VERSION 5.7 ;
BUSBITCHARS "[]" ;
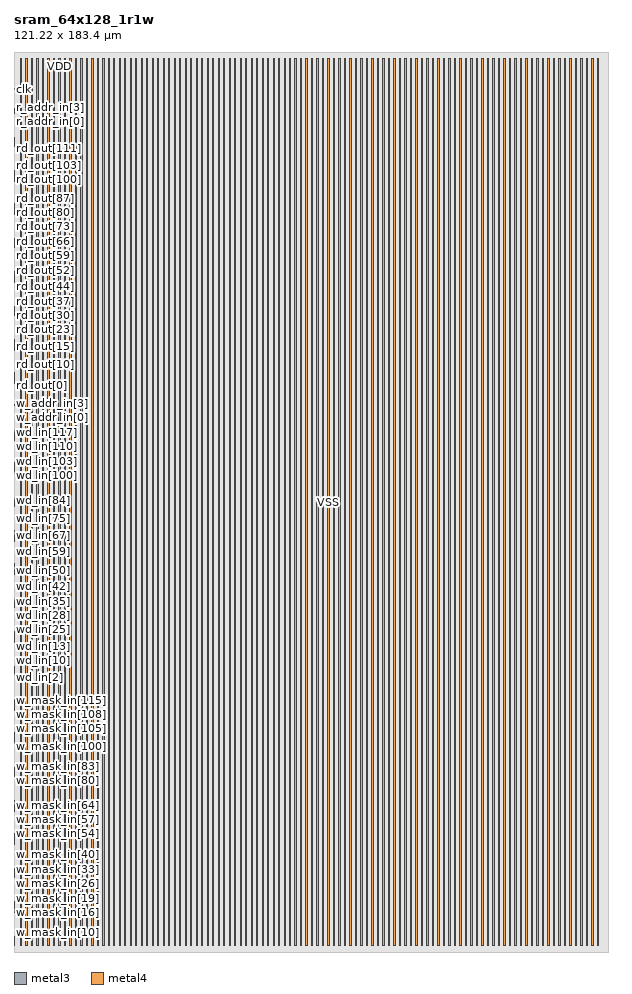
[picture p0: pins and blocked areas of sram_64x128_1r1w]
MACRO sram_64x128_1r1w
  FOREIGN sram_64x128_1r1w 0 0 ;
  SYMMETRY X Y R90 ;
  SIZE 121.220 BY 183.400 ;
  CLASS BLOCK ;
  PIN w_mask_in[0]
    DIRECTION INPUT ;
    USE SIGNAL ;
    SHAPE ABUTMENT ;
    PORT
      LAYER metal3 ;
      RECT 0.000 1.365 0.070 1.435 ;
    END
  END w_mask_in[0]
  PIN w_mask_in[1]
    DIRECTION INPUT ;
    USE SIGNAL ;
    SHAPE ABUTMENT ;
    PORT
      LAYER metal3 ;
      RECT 0.000 1.785 0.070 1.855 ;
    END
  END w_mask_in[1]
  PIN w_mask_in[2]
    DIRECTION INPUT ;
    USE SIGNAL ;
    SHAPE ABUTMENT ;
    PORT
      LAYER metal3 ;
      RECT 0.000 2.205 0.070 2.275 ;
    END
  END w_mask_in[2]
  PIN w_mask_in[3]
    DIRECTION INPUT ;
    USE SIGNAL ;
    SHAPE ABUTMENT ;
    PORT
      LAYER metal3 ;
      RECT 0.000 2.625 0.070 2.695 ;
    END
  END w_mask_in[3]
  PIN w_mask_in[4]
    DIRECTION INPUT ;
    USE SIGNAL ;
    SHAPE ABUTMENT ;
    PORT
      LAYER metal3 ;
      RECT 0.000 3.045 0.070 3.115 ;
    END
  END w_mask_in[4]
  PIN w_mask_in[5]
    DIRECTION INPUT ;
    USE SIGNAL ;
    SHAPE ABUTMENT ;
    PORT
      LAYER metal3 ;
      RECT 0.000 3.465 0.070 3.535 ;
    END
  END w_mask_in[5]
  PIN w_mask_in[6]
    DIRECTION INPUT ;
    USE SIGNAL ;
    SHAPE ABUTMENT ;
    PORT
      LAYER metal3 ;
      RECT 0.000 3.885 0.070 3.955 ;
    END
  END w_mask_in[6]
  PIN w_mask_in[7]
    DIRECTION INPUT ;
    USE SIGNAL ;
    SHAPE ABUTMENT ;
    PORT
      LAYER metal3 ;
      RECT 0.000 4.305 0.070 4.375 ;
    END
  END w_mask_in[7]
  PIN w_mask_in[8]
    DIRECTION INPUT ;
    USE SIGNAL ;
    SHAPE ABUTMENT ;
    PORT
      LAYER metal3 ;
      RECT 0.000 4.725 0.070 4.795 ;
    END
  END w_mask_in[8]
  PIN w_mask_in[9]
    DIRECTION INPUT ;
    USE SIGNAL ;
    SHAPE ABUTMENT ;
    PORT
      LAYER metal3 ;
      RECT 0.000 5.145 0.070 5.215 ;
    END
  END w_mask_in[9]
  PIN w_mask_in[10]
    DIRECTION INPUT ;
    USE SIGNAL ;
    SHAPE ABUTMENT ;
    PORT
      LAYER metal3 ;
      RECT 0.000 5.565 0.070 5.635 ;
    END
  END w_mask_in[10]
  PIN w_mask_in[11]
    DIRECTION INPUT ;
    USE SIGNAL ;
    SHAPE ABUTMENT ;
    PORT
      LAYER metal3 ;
      RECT 0.000 5.985 0.070 6.055 ;
    END
  END w_mask_in[11]
  PIN w_mask_in[12]
    DIRECTION INPUT ;
    USE SIGNAL ;
    SHAPE ABUTMENT ;
    PORT
      LAYER metal3 ;
      RECT 0.000 6.405 0.070 6.475 ;
    END
  END w_mask_in[12]
  PIN w_mask_in[13]
    DIRECTION INPUT ;
    USE SIGNAL ;
    SHAPE ABUTMENT ;
    PORT
      LAYER metal3 ;
      RECT 0.000 6.825 0.070 6.895 ;
    END
  END w_mask_in[13]
  PIN w_mask_in[14]
    DIRECTION INPUT ;
    USE SIGNAL ;
    SHAPE ABUTMENT ;
    PORT
      LAYER metal3 ;
      RECT 0.000 7.245 0.070 7.315 ;
    END
  END w_mask_in[14]
  PIN w_mask_in[15]
    DIRECTION INPUT ;
    USE SIGNAL ;
    SHAPE ABUTMENT ;
    PORT
      LAYER metal3 ;
      RECT 0.000 7.665 0.070 7.735 ;
    END
  END w_mask_in[15]
  PIN w_mask_in[16]
    DIRECTION INPUT ;
    USE SIGNAL ;
    SHAPE ABUTMENT ;
    PORT
      LAYER metal3 ;
      RECT 0.000 8.085 0.070 8.155 ;
    END
  END w_mask_in[16]
  PIN w_mask_in[17]
    DIRECTION INPUT ;
    USE SIGNAL ;
    SHAPE ABUTMENT ;
    PORT
      LAYER metal3 ;
      RECT 0.000 8.505 0.070 8.575 ;
    END
  END w_mask_in[17]
  PIN w_mask_in[18]
    DIRECTION INPUT ;
    USE SIGNAL ;
    SHAPE ABUTMENT ;
    PORT
      LAYER metal3 ;
      RECT 0.000 8.925 0.070 8.995 ;
    END
  END w_mask_in[18]
  PIN w_mask_in[19]
    DIRECTION INPUT ;
    USE SIGNAL ;
    SHAPE ABUTMENT ;
    PORT
      LAYER metal3 ;
      RECT 0.000 9.345 0.070 9.415 ;
    END
  END w_mask_in[19]
  PIN w_mask_in[20]
    DIRECTION INPUT ;
    USE SIGNAL ;
    SHAPE ABUTMENT ;
    PORT
      LAYER metal3 ;
      RECT 0.000 9.765 0.070 9.835 ;
    END
  END w_mask_in[20]
  PIN w_mask_in[21]
    DIRECTION INPUT ;
    USE SIGNAL ;
    SHAPE ABUTMENT ;
    PORT
      LAYER metal3 ;
      RECT 0.000 10.185 0.070 10.255 ;
    END
  END w_mask_in[21]
  PIN w_mask_in[22]
    DIRECTION INPUT ;
    USE SIGNAL ;
    SHAPE ABUTMENT ;
    PORT
      LAYER metal3 ;
      RECT 0.000 10.605 0.070 10.675 ;
    END
  END w_mask_in[22]
  PIN w_mask_in[23]
    DIRECTION INPUT ;
    USE SIGNAL ;
    SHAPE ABUTMENT ;
    PORT
      LAYER metal3 ;
      RECT 0.000 11.025 0.070 11.095 ;
    END
  END w_mask_in[23]
  PIN w_mask_in[24]
    DIRECTION INPUT ;
    USE SIGNAL ;
    SHAPE ABUTMENT ;
    PORT
      LAYER metal3 ;
      RECT 0.000 11.445 0.070 11.515 ;
    END
  END w_mask_in[24]
  PIN w_mask_in[25]
    DIRECTION INPUT ;
    USE SIGNAL ;
    SHAPE ABUTMENT ;
    PORT
      LAYER metal3 ;
      RECT 0.000 11.865 0.070 11.935 ;
    END
  END w_mask_in[25]
  PIN w_mask_in[26]
    DIRECTION INPUT ;
    USE SIGNAL ;
    SHAPE ABUTMENT ;
    PORT
      LAYER metal3 ;
      RECT 0.000 12.285 0.070 12.355 ;
    END
  END w_mask_in[26]
  PIN w_mask_in[27]
    DIRECTION INPUT ;
    USE SIGNAL ;
    SHAPE ABUTMENT ;
    PORT
      LAYER metal3 ;
      RECT 0.000 12.705 0.070 12.775 ;
    END
  END w_mask_in[27]
  PIN w_mask_in[28]
    DIRECTION INPUT ;
    USE SIGNAL ;
    SHAPE ABUTMENT ;
    PORT
      LAYER metal3 ;
      RECT 0.000 13.125 0.070 13.195 ;
    END
  END w_mask_in[28]
  PIN w_mask_in[29]
    DIRECTION INPUT ;
    USE SIGNAL ;
    SHAPE ABUTMENT ;
    PORT
      LAYER metal3 ;
      RECT 0.000 13.545 0.070 13.615 ;
    END
  END w_mask_in[29]
  PIN w_mask_in[30]
    DIRECTION INPUT ;
    USE SIGNAL ;
    SHAPE ABUTMENT ;
    PORT
      LAYER metal3 ;
      RECT 0.000 13.965 0.070 14.035 ;
    END
  END w_mask_in[30]
  PIN w_mask_in[31]
    DIRECTION INPUT ;
    USE SIGNAL ;
    SHAPE ABUTMENT ;
    PORT
      LAYER metal3 ;
      RECT 0.000 14.385 0.070 14.455 ;
    END
  END w_mask_in[31]
  PIN w_mask_in[32]
    DIRECTION INPUT ;
    USE SIGNAL ;
    SHAPE ABUTMENT ;
    PORT
      LAYER metal3 ;
      RECT 0.000 14.805 0.070 14.875 ;
    END
  END w_mask_in[32]
  PIN w_mask_in[33]
    DIRECTION INPUT ;
    USE SIGNAL ;
    SHAPE ABUTMENT ;
    PORT
      LAYER metal3 ;
      RECT 0.000 15.225 0.070 15.295 ;
    END
  END w_mask_in[33]
  PIN w_mask_in[34]
    DIRECTION INPUT ;
    USE SIGNAL ;
    SHAPE ABUTMENT ;
    PORT
      LAYER metal3 ;
      RECT 0.000 15.645 0.070 15.715 ;
    END
  END w_mask_in[34]
  PIN w_mask_in[35]
    DIRECTION INPUT ;
    USE SIGNAL ;
    SHAPE ABUTMENT ;
    PORT
      LAYER metal3 ;
      RECT 0.000 16.065 0.070 16.135 ;
    END
  END w_mask_in[35]
  PIN w_mask_in[36]
    DIRECTION INPUT ;
    USE SIGNAL ;
    SHAPE ABUTMENT ;
    PORT
      LAYER metal3 ;
      RECT 0.000 16.485 0.070 16.555 ;
    END
  END w_mask_in[36]
  PIN w_mask_in[37]
    DIRECTION INPUT ;
    USE SIGNAL ;
    SHAPE ABUTMENT ;
    PORT
      LAYER metal3 ;
      RECT 0.000 16.905 0.070 16.975 ;
    END
  END w_mask_in[37]
  PIN w_mask_in[38]
    DIRECTION INPUT ;
    USE SIGNAL ;
    SHAPE ABUTMENT ;
    PORT
      LAYER metal3 ;
      RECT 0.000 17.325 0.070 17.395 ;
    END
  END w_mask_in[38]
  PIN w_mask_in[39]
    DIRECTION INPUT ;
    USE SIGNAL ;
    SHAPE ABUTMENT ;
    PORT
      LAYER metal3 ;
      RECT 0.000 17.745 0.070 17.815 ;
    END
  END w_mask_in[39]
  PIN w_mask_in[40]
    DIRECTION INPUT ;
    USE SIGNAL ;
    SHAPE ABUTMENT ;
    PORT
      LAYER metal3 ;
      RECT 0.000 18.165 0.070 18.235 ;
    END
  END w_mask_in[40]
  PIN w_mask_in[41]
    DIRECTION INPUT ;
    USE SIGNAL ;
    SHAPE ABUTMENT ;
    PORT
      LAYER metal3 ;
      RECT 0.000 18.585 0.070 18.655 ;
    END
  END w_mask_in[41]
  PIN w_mask_in[42]
    DIRECTION INPUT ;
    USE SIGNAL ;
    SHAPE ABUTMENT ;
    PORT
      LAYER metal3 ;
      RECT 0.000 19.005 0.070 19.075 ;
    END
  END w_mask_in[42]
  PIN w_mask_in[43]
    DIRECTION INPUT ;
    USE SIGNAL ;
    SHAPE ABUTMENT ;
    PORT
      LAYER metal3 ;
      RECT 0.000 19.425 0.070 19.495 ;
    END
  END w_mask_in[43]
  PIN w_mask_in[44]
    DIRECTION INPUT ;
    USE SIGNAL ;
    SHAPE ABUTMENT ;
    PORT
      LAYER metal3 ;
      RECT 0.000 19.845 0.070 19.915 ;
    END
  END w_mask_in[44]
  PIN w_mask_in[45]
    DIRECTION INPUT ;
    USE SIGNAL ;
    SHAPE ABUTMENT ;
    PORT
      LAYER metal3 ;
      RECT 0.000 20.265 0.070 20.335 ;
    END
  END w_mask_in[45]
  PIN w_mask_in[46]
    DIRECTION INPUT ;
    USE SIGNAL ;
    SHAPE ABUTMENT ;
    PORT
      LAYER metal3 ;
      RECT 0.000 20.685 0.070 20.755 ;
    END
  END w_mask_in[46]
  PIN w_mask_in[47]
    DIRECTION INPUT ;
    USE SIGNAL ;
    SHAPE ABUTMENT ;
    PORT
      LAYER metal3 ;
      RECT 0.000 21.105 0.070 21.175 ;
    END
  END w_mask_in[47]
  PIN w_mask_in[48]
    DIRECTION INPUT ;
    USE SIGNAL ;
    SHAPE ABUTMENT ;
    PORT
      LAYER metal3 ;
      RECT 0.000 21.525 0.070 21.595 ;
    END
  END w_mask_in[48]
  PIN w_mask_in[49]
    DIRECTION INPUT ;
    USE SIGNAL ;
    SHAPE ABUTMENT ;
    PORT
      LAYER metal3 ;
      RECT 0.000 21.945 0.070 22.015 ;
    END
  END w_mask_in[49]
  PIN w_mask_in[50]
    DIRECTION INPUT ;
    USE SIGNAL ;
    SHAPE ABUTMENT ;
    PORT
      LAYER metal3 ;
      RECT 0.000 22.365 0.070 22.435 ;
    END
  END w_mask_in[50]
  PIN w_mask_in[51]
    DIRECTION INPUT ;
    USE SIGNAL ;
    SHAPE ABUTMENT ;
    PORT
      LAYER metal3 ;
      RECT 0.000 22.785 0.070 22.855 ;
    END
  END w_mask_in[51]
  PIN w_mask_in[52]
    DIRECTION INPUT ;
    USE SIGNAL ;
    SHAPE ABUTMENT ;
    PORT
      LAYER metal3 ;
      RECT 0.000 23.205 0.070 23.275 ;
    END
  END w_mask_in[52]
  PIN w_mask_in[53]
    DIRECTION INPUT ;
    USE SIGNAL ;
    SHAPE ABUTMENT ;
    PORT
      LAYER metal3 ;
      RECT 0.000 23.625 0.070 23.695 ;
    END
  END w_mask_in[53]
  PIN w_mask_in[54]
    DIRECTION INPUT ;
    USE SIGNAL ;
    SHAPE ABUTMENT ;
    PORT
      LAYER metal3 ;
      RECT 0.000 24.045 0.070 24.115 ;
    END
  END w_mask_in[54]
  PIN w_mask_in[55]
    DIRECTION INPUT ;
    USE SIGNAL ;
    SHAPE ABUTMENT ;
    PORT
      LAYER metal3 ;
      RECT 0.000 24.465 0.070 24.535 ;
    END
  END w_mask_in[55]
  PIN w_mask_in[56]
    DIRECTION INPUT ;
    USE SIGNAL ;
    SHAPE ABUTMENT ;
    PORT
      LAYER metal3 ;
      RECT 0.000 24.885 0.070 24.955 ;
    END
  END w_mask_in[56]
  PIN w_mask_in[57]
    DIRECTION INPUT ;
    USE SIGNAL ;
    SHAPE ABUTMENT ;
    PORT
      LAYER metal3 ;
      RECT 0.000 25.305 0.070 25.375 ;
    END
  END w_mask_in[57]
  PIN w_mask_in[58]
    DIRECTION INPUT ;
    USE SIGNAL ;
    SHAPE ABUTMENT ;
    PORT
      LAYER metal3 ;
      RECT 0.000 25.725 0.070 25.795 ;
    END
  END w_mask_in[58]
  PIN w_mask_in[59]
    DIRECTION INPUT ;
    USE SIGNAL ;
    SHAPE ABUTMENT ;
    PORT
      LAYER metal3 ;
      RECT 0.000 26.145 0.070 26.215 ;
    END
  END w_mask_in[59]
  PIN w_mask_in[60]
    DIRECTION INPUT ;
    USE SIGNAL ;
    SHAPE ABUTMENT ;
    PORT
      LAYER metal3 ;
      RECT 0.000 26.565 0.070 26.635 ;
    END
  END w_mask_in[60]
  PIN w_mask_in[61]
    DIRECTION INPUT ;
    USE SIGNAL ;
    SHAPE ABUTMENT ;
    PORT
      LAYER metal3 ;
      RECT 0.000 26.985 0.070 27.055 ;
    END
  END w_mask_in[61]
  PIN w_mask_in[62]
    DIRECTION INPUT ;
    USE SIGNAL ;
    SHAPE ABUTMENT ;
    PORT
      LAYER metal3 ;
      RECT 0.000 27.405 0.070 27.475 ;
    END
  END w_mask_in[62]
  PIN w_mask_in[63]
    DIRECTION INPUT ;
    USE SIGNAL ;
    SHAPE ABUTMENT ;
    PORT
      LAYER metal3 ;
      RECT 0.000 27.825 0.070 27.895 ;
    END
  END w_mask_in[63]
  PIN w_mask_in[64]
    DIRECTION INPUT ;
    USE SIGNAL ;
    SHAPE ABUTMENT ;
    PORT
      LAYER metal3 ;
      RECT 0.000 28.245 0.070 28.315 ;
    END
  END w_mask_in[64]
  PIN w_mask_in[65]
    DIRECTION INPUT ;
    USE SIGNAL ;
    SHAPE ABUTMENT ;
    PORT
      LAYER metal3 ;
      RECT 0.000 28.665 0.070 28.735 ;
    END
  END w_mask_in[65]
  PIN w_mask_in[66]
    DIRECTION INPUT ;
    USE SIGNAL ;
    SHAPE ABUTMENT ;
    PORT
      LAYER metal3 ;
      RECT 0.000 29.085 0.070 29.155 ;
    END
  END w_mask_in[66]
  PIN w_mask_in[67]
    DIRECTION INPUT ;
    USE SIGNAL ;
    SHAPE ABUTMENT ;
    PORT
      LAYER metal3 ;
      RECT 0.000 29.505 0.070 29.575 ;
    END
  END w_mask_in[67]
  PIN w_mask_in[68]
    DIRECTION INPUT ;
    USE SIGNAL ;
    SHAPE ABUTMENT ;
    PORT
      LAYER metal3 ;
      RECT 0.000 29.925 0.070 29.995 ;
    END
  END w_mask_in[68]
  PIN w_mask_in[69]
    DIRECTION INPUT ;
    USE SIGNAL ;
    SHAPE ABUTMENT ;
    PORT
      LAYER metal3 ;
      RECT 0.000 30.345 0.070 30.415 ;
    END
  END w_mask_in[69]
  PIN w_mask_in[70]
    DIRECTION INPUT ;
    USE SIGNAL ;
    SHAPE ABUTMENT ;
    PORT
      LAYER metal3 ;
      RECT 0.000 30.765 0.070 30.835 ;
    END
  END w_mask_in[70]
  PIN w_mask_in[71]
    DIRECTION INPUT ;
    USE SIGNAL ;
    SHAPE ABUTMENT ;
    PORT
      LAYER metal3 ;
      RECT 0.000 31.185 0.070 31.255 ;
    END
  END w_mask_in[71]
  PIN w_mask_in[72]
    DIRECTION INPUT ;
    USE SIGNAL ;
    SHAPE ABUTMENT ;
    PORT
      LAYER metal3 ;
      RECT 0.000 31.605 0.070 31.675 ;
    END
  END w_mask_in[72]
  PIN w_mask_in[73]
    DIRECTION INPUT ;
    USE SIGNAL ;
    SHAPE ABUTMENT ;
    PORT
      LAYER metal3 ;
      RECT 0.000 32.025 0.070 32.095 ;
    END
  END w_mask_in[73]
  PIN w_mask_in[74]
    DIRECTION INPUT ;
    USE SIGNAL ;
    SHAPE ABUTMENT ;
    PORT
      LAYER metal3 ;
      RECT 0.000 32.445 0.070 32.515 ;
    END
  END w_mask_in[74]
  PIN w_mask_in[75]
    DIRECTION INPUT ;
    USE SIGNAL ;
    SHAPE ABUTMENT ;
    PORT
      LAYER metal3 ;
      RECT 0.000 32.865 0.070 32.935 ;
    END
  END w_mask_in[75]
  PIN w_mask_in[76]
    DIRECTION INPUT ;
    USE SIGNAL ;
    SHAPE ABUTMENT ;
    PORT
      LAYER metal3 ;
      RECT 0.000 33.285 0.070 33.355 ;
    END
  END w_mask_in[76]
  PIN w_mask_in[77]
    DIRECTION INPUT ;
    USE SIGNAL ;
    SHAPE ABUTMENT ;
    PORT
      LAYER metal3 ;
      RECT 0.000 33.705 0.070 33.775 ;
    END
  END w_mask_in[77]
  PIN w_mask_in[78]
    DIRECTION INPUT ;
    USE SIGNAL ;
    SHAPE ABUTMENT ;
    PORT
      LAYER metal3 ;
      RECT 0.000 34.125 0.070 34.195 ;
    END
  END w_mask_in[78]
  PIN w_mask_in[79]
    DIRECTION INPUT ;
    USE SIGNAL ;
    SHAPE ABUTMENT ;
    PORT
      LAYER metal3 ;
      RECT 0.000 34.545 0.070 34.615 ;
    END
  END w_mask_in[79]
  PIN w_mask_in[80]
    DIRECTION INPUT ;
    USE SIGNAL ;
    SHAPE ABUTMENT ;
    PORT
      LAYER metal3 ;
      RECT 0.000 34.965 0.070 35.035 ;
    END
  END w_mask_in[80]
  PIN w_mask_in[81]
    DIRECTION INPUT ;
    USE SIGNAL ;
    SHAPE ABUTMENT ;
    PORT
      LAYER metal3 ;
      RECT 0.000 35.385 0.070 35.455 ;
    END
  END w_mask_in[81]
  PIN w_mask_in[82]
    DIRECTION INPUT ;
    USE SIGNAL ;
    SHAPE ABUTMENT ;
    PORT
      LAYER metal3 ;
      RECT 0.000 35.805 0.070 35.875 ;
    END
  END w_mask_in[82]
  PIN w_mask_in[83]
    DIRECTION INPUT ;
    USE SIGNAL ;
    SHAPE ABUTMENT ;
    PORT
      LAYER metal3 ;
      RECT 0.000 36.225 0.070 36.295 ;
    END
  END w_mask_in[83]
  PIN w_mask_in[84]
    DIRECTION INPUT ;
    USE SIGNAL ;
    SHAPE ABUTMENT ;
    PORT
      LAYER metal3 ;
      RECT 0.000 36.645 0.070 36.715 ;
    END
  END w_mask_in[84]
  PIN w_mask_in[85]
    DIRECTION INPUT ;
    USE SIGNAL ;
    SHAPE ABUTMENT ;
    PORT
      LAYER metal3 ;
      RECT 0.000 37.065 0.070 37.135 ;
    END
  END w_mask_in[85]
  PIN w_mask_in[86]
    DIRECTION INPUT ;
    USE SIGNAL ;
    SHAPE ABUTMENT ;
    PORT
      LAYER metal3 ;
      RECT 0.000 37.485 0.070 37.555 ;
    END
  END w_mask_in[86]
  PIN w_mask_in[87]
    DIRECTION INPUT ;
    USE SIGNAL ;
    SHAPE ABUTMENT ;
    PORT
      LAYER metal3 ;
      RECT 0.000 37.905 0.070 37.975 ;
    END
  END w_mask_in[87]
  PIN w_mask_in[88]
    DIRECTION INPUT ;
    USE SIGNAL ;
    SHAPE ABUTMENT ;
    PORT
      LAYER metal3 ;
      RECT 0.000 38.325 0.070 38.395 ;
    END
  END w_mask_in[88]
  PIN w_mask_in[89]
    DIRECTION INPUT ;
    USE SIGNAL ;
    SHAPE ABUTMENT ;
    PORT
      LAYER metal3 ;
      RECT 0.000 38.745 0.070 38.815 ;
    END
  END w_mask_in[89]
  PIN w_mask_in[90]
    DIRECTION INPUT ;
    USE SIGNAL ;
    SHAPE ABUTMENT ;
    PORT
      LAYER metal3 ;
      RECT 0.000 39.165 0.070 39.235 ;
    END
  END w_mask_in[90]
  PIN w_mask_in[91]
    DIRECTION INPUT ;
    USE SIGNAL ;
    SHAPE ABUTMENT ;
    PORT
      LAYER metal3 ;
      RECT 0.000 39.585 0.070 39.655 ;
    END
  END w_mask_in[91]
  PIN w_mask_in[92]
    DIRECTION INPUT ;
    USE SIGNAL ;
    SHAPE ABUTMENT ;
    PORT
      LAYER metal3 ;
      RECT 0.000 40.005 0.070 40.075 ;
    END
  END w_mask_in[92]
  PIN w_mask_in[93]
    DIRECTION INPUT ;
    USE SIGNAL ;
    SHAPE ABUTMENT ;
    PORT
      LAYER metal3 ;
      RECT 0.000 40.425 0.070 40.495 ;
    END
  END w_mask_in[93]
  PIN w_mask_in[94]
    DIRECTION INPUT ;
    USE SIGNAL ;
    SHAPE ABUTMENT ;
    PORT
      LAYER metal3 ;
      RECT 0.000 40.845 0.070 40.915 ;
    END
  END w_mask_in[94]
  PIN w_mask_in[95]
    DIRECTION INPUT ;
    USE SIGNAL ;
    SHAPE ABUTMENT ;
    PORT
      LAYER metal3 ;
      RECT 0.000 41.265 0.070 41.335 ;
    END
  END w_mask_in[95]
  PIN w_mask_in[96]
    DIRECTION INPUT ;
    USE SIGNAL ;
    SHAPE ABUTMENT ;
    PORT
      LAYER metal3 ;
      RECT 0.000 41.685 0.070 41.755 ;
    END
  END w_mask_in[96]
  PIN w_mask_in[97]
    DIRECTION INPUT ;
    USE SIGNAL ;
    SHAPE ABUTMENT ;
    PORT
      LAYER metal3 ;
      RECT 0.000 42.105 0.070 42.175 ;
    END
  END w_mask_in[97]
  PIN w_mask_in[98]
    DIRECTION INPUT ;
    USE SIGNAL ;
    SHAPE ABUTMENT ;
    PORT
      LAYER metal3 ;
      RECT 0.000 42.525 0.070 42.595 ;
    END
  END w_mask_in[98]
  PIN w_mask_in[99]
    DIRECTION INPUT ;
    USE SIGNAL ;
    SHAPE ABUTMENT ;
    PORT
      LAYER metal3 ;
      RECT 0.000 42.945 0.070 43.015 ;
    END
  END w_mask_in[99]
  PIN w_mask_in[100]
    DIRECTION INPUT ;
    USE SIGNAL ;
    SHAPE ABUTMENT ;
    PORT
      LAYER metal3 ;
      RECT 0.000 43.365 0.070 43.435 ;
    END
  END w_mask_in[100]
  PIN w_mask_in[101]
    DIRECTION INPUT ;
    USE SIGNAL ;
    SHAPE ABUTMENT ;
    PORT
      LAYER metal3 ;
      RECT 0.000 43.785 0.070 43.855 ;
    END
  END w_mask_in[101]
  PIN w_mask_in[102]
    DIRECTION INPUT ;
    USE SIGNAL ;
    SHAPE ABUTMENT ;
    PORT
      LAYER metal3 ;
      RECT 0.000 44.205 0.070 44.275 ;
    END
  END w_mask_in[102]
  PIN w_mask_in[103]
    DIRECTION INPUT ;
    USE SIGNAL ;
    SHAPE ABUTMENT ;
    PORT
      LAYER metal3 ;
      RECT 0.000 44.625 0.070 44.695 ;
    END
  END w_mask_in[103]
  PIN w_mask_in[104]
    DIRECTION INPUT ;
    USE SIGNAL ;
    SHAPE ABUTMENT ;
    PORT
      LAYER metal3 ;
      RECT 0.000 45.045 0.070 45.115 ;
    END
  END w_mask_in[104]
  PIN w_mask_in[105]
    DIRECTION INPUT ;
    USE SIGNAL ;
    SHAPE ABUTMENT ;
    PORT
      LAYER metal3 ;
      RECT 0.000 45.465 0.070 45.535 ;
    END
  END w_mask_in[105]
  PIN w_mask_in[106]
    DIRECTION INPUT ;
    USE SIGNAL ;
    SHAPE ABUTMENT ;
    PORT
      LAYER metal3 ;
      RECT 0.000 45.885 0.070 45.955 ;
    END
  END w_mask_in[106]
  PIN w_mask_in[107]
    DIRECTION INPUT ;
    USE SIGNAL ;
    SHAPE ABUTMENT ;
    PORT
      LAYER metal3 ;
      RECT 0.000 46.305 0.070 46.375 ;
    END
  END w_mask_in[107]
  PIN w_mask_in[108]
    DIRECTION INPUT ;
    USE SIGNAL ;
    SHAPE ABUTMENT ;
    PORT
      LAYER metal3 ;
      RECT 0.000 46.725 0.070 46.795 ;
    END
  END w_mask_in[108]
  PIN w_mask_in[109]
    DIRECTION INPUT ;
    USE SIGNAL ;
    SHAPE ABUTMENT ;
    PORT
      LAYER metal3 ;
      RECT 0.000 47.145 0.070 47.215 ;
    END
  END w_mask_in[109]
  PIN w_mask_in[110]
    DIRECTION INPUT ;
    USE SIGNAL ;
    SHAPE ABUTMENT ;
    PORT
      LAYER metal3 ;
      RECT 0.000 47.565 0.070 47.635 ;
    END
  END w_mask_in[110]
  PIN w_mask_in[111]
    DIRECTION INPUT ;
    USE SIGNAL ;
    SHAPE ABUTMENT ;
    PORT
      LAYER metal3 ;
      RECT 0.000 47.985 0.070 48.055 ;
    END
  END w_mask_in[111]
  PIN w_mask_in[112]
    DIRECTION INPUT ;
    USE SIGNAL ;
    SHAPE ABUTMENT ;
    PORT
      LAYER metal3 ;
      RECT 0.000 48.405 0.070 48.475 ;
    END
  END w_mask_in[112]
  PIN w_mask_in[113]
    DIRECTION INPUT ;
    USE SIGNAL ;
    SHAPE ABUTMENT ;
    PORT
      LAYER metal3 ;
      RECT 0.000 48.825 0.070 48.895 ;
    END
  END w_mask_in[113]
  PIN w_mask_in[114]
    DIRECTION INPUT ;
    USE SIGNAL ;
    SHAPE ABUTMENT ;
    PORT
      LAYER metal3 ;
      RECT 0.000 49.245 0.070 49.315 ;
    END
  END w_mask_in[114]
  PIN w_mask_in[115]
    DIRECTION INPUT ;
    USE SIGNAL ;
    SHAPE ABUTMENT ;
    PORT
      LAYER metal3 ;
      RECT 0.000 49.665 0.070 49.735 ;
    END
  END w_mask_in[115]
  PIN w_mask_in[116]
    DIRECTION INPUT ;
    USE SIGNAL ;
    SHAPE ABUTMENT ;
    PORT
      LAYER metal3 ;
      RECT 0.000 50.085 0.070 50.155 ;
    END
  END w_mask_in[116]
  PIN w_mask_in[117]
    DIRECTION INPUT ;
    USE SIGNAL ;
    SHAPE ABUTMENT ;
    PORT
      LAYER metal3 ;
      RECT 0.000 50.505 0.070 50.575 ;
    END
  END w_mask_in[117]
  PIN w_mask_in[118]
    DIRECTION INPUT ;
    USE SIGNAL ;
    SHAPE ABUTMENT ;
    PORT
      LAYER metal3 ;
      RECT 0.000 50.925 0.070 50.995 ;
    END
  END w_mask_in[118]
  PIN w_mask_in[119]
    DIRECTION INPUT ;
    USE SIGNAL ;
    SHAPE ABUTMENT ;
    PORT
      LAYER metal3 ;
      RECT 0.000 51.345 0.070 51.415 ;
    END
  END w_mask_in[119]
  PIN w_mask_in[120]
    DIRECTION INPUT ;
    USE SIGNAL ;
    SHAPE ABUTMENT ;
    PORT
      LAYER metal3 ;
      RECT 0.000 51.765 0.070 51.835 ;
    END
  END w_mask_in[120]
  PIN w_mask_in[121]
    DIRECTION INPUT ;
    USE SIGNAL ;
    SHAPE ABUTMENT ;
    PORT
      LAYER metal3 ;
      RECT 0.000 52.185 0.070 52.255 ;
    END
  END w_mask_in[121]
  PIN w_mask_in[122]
    DIRECTION INPUT ;
    USE SIGNAL ;
    SHAPE ABUTMENT ;
    PORT
      LAYER metal3 ;
      RECT 0.000 52.605 0.070 52.675 ;
    END
  END w_mask_in[122]
  PIN w_mask_in[123]
    DIRECTION INPUT ;
    USE SIGNAL ;
    SHAPE ABUTMENT ;
    PORT
      LAYER metal3 ;
      RECT 0.000 53.025 0.070 53.095 ;
    END
  END w_mask_in[123]
  PIN w_mask_in[124]
    DIRECTION INPUT ;
    USE SIGNAL ;
    SHAPE ABUTMENT ;
    PORT
      LAYER metal3 ;
      RECT 0.000 53.445 0.070 53.515 ;
    END
  END w_mask_in[124]
  PIN w_mask_in[125]
    DIRECTION INPUT ;
    USE SIGNAL ;
    SHAPE ABUTMENT ;
    PORT
      LAYER metal3 ;
      RECT 0.000 53.865 0.070 53.935 ;
    END
  END w_mask_in[125]
  PIN w_mask_in[126]
    DIRECTION INPUT ;
    USE SIGNAL ;
    SHAPE ABUTMENT ;
    PORT
      LAYER metal3 ;
      RECT 0.000 54.285 0.070 54.355 ;
    END
  END w_mask_in[126]
  PIN w_mask_in[127]
    DIRECTION INPUT ;
    USE SIGNAL ;
    SHAPE ABUTMENT ;
    PORT
      LAYER metal3 ;
      RECT 0.000 54.705 0.070 54.775 ;
    END
  END w_mask_in[127]
  PIN wd_in[0]
    DIRECTION INPUT ;
    USE SIGNAL ;
    SHAPE ABUTMENT ;
    PORT
      LAYER metal3 ;
      RECT 0.000 55.125 0.070 55.195 ;
    END
  END wd_in[0]
  PIN wd_in[1]
    DIRECTION INPUT ;
    USE SIGNAL ;
    SHAPE ABUTMENT ;
    PORT
      LAYER metal3 ;
      RECT 0.000 55.545 0.070 55.615 ;
    END
  END wd_in[1]
  PIN wd_in[2]
    DIRECTION INPUT ;
    USE SIGNAL ;
    SHAPE ABUTMENT ;
    PORT
      LAYER metal3 ;
      RECT 0.000 55.965 0.070 56.035 ;
    END
  END wd_in[2]
  PIN wd_in[3]
    DIRECTION INPUT ;
    USE SIGNAL ;
    SHAPE ABUTMENT ;
    PORT
      LAYER metal3 ;
      RECT 0.000 56.385 0.070 56.455 ;
    END
  END wd_in[3]
  PIN wd_in[4]
    DIRECTION INPUT ;
    USE SIGNAL ;
    SHAPE ABUTMENT ;
    PORT
      LAYER metal3 ;
      RECT 0.000 56.805 0.070 56.875 ;
    END
  END wd_in[4]
  PIN wd_in[5]
    DIRECTION INPUT ;
    USE SIGNAL ;
    SHAPE ABUTMENT ;
    PORT
      LAYER metal3 ;
      RECT 0.000 57.225 0.070 57.295 ;
    END
  END wd_in[5]
  PIN wd_in[6]
    DIRECTION INPUT ;
    USE SIGNAL ;
    SHAPE ABUTMENT ;
    PORT
      LAYER metal3 ;
      RECT 0.000 57.645 0.070 57.715 ;
    END
  END wd_in[6]
  PIN wd_in[7]
    DIRECTION INPUT ;
    USE SIGNAL ;
    SHAPE ABUTMENT ;
    PORT
      LAYER metal3 ;
      RECT 0.000 58.065 0.070 58.135 ;
    END
  END wd_in[7]
  PIN wd_in[8]
    DIRECTION INPUT ;
    USE SIGNAL ;
    SHAPE ABUTMENT ;
    PORT
      LAYER metal3 ;
      RECT 0.000 58.485 0.070 58.555 ;
    END
  END wd_in[8]
  PIN wd_in[9]
    DIRECTION INPUT ;
    USE SIGNAL ;
    SHAPE ABUTMENT ;
    PORT
      LAYER metal3 ;
      RECT 0.000 58.905 0.070 58.975 ;
    END
  END wd_in[9]
  PIN wd_in[10]
    DIRECTION INPUT ;
    USE SIGNAL ;
    SHAPE ABUTMENT ;
    PORT
      LAYER metal3 ;
      RECT 0.000 59.325 0.070 59.395 ;
    END
  END wd_in[10]
  PIN wd_in[11]
    DIRECTION INPUT ;
    USE SIGNAL ;
    SHAPE ABUTMENT ;
    PORT
      LAYER metal3 ;
      RECT 0.000 59.745 0.070 59.815 ;
    END
  END wd_in[11]
  PIN wd_in[12]
    DIRECTION INPUT ;
    USE SIGNAL ;
    SHAPE ABUTMENT ;
    PORT
      LAYER metal3 ;
      RECT 0.000 60.165 0.070 60.235 ;
    END
  END wd_in[12]
  PIN wd_in[13]
    DIRECTION INPUT ;
    USE SIGNAL ;
    SHAPE ABUTMENT ;
    PORT
      LAYER metal3 ;
      RECT 0.000 60.585 0.070 60.655 ;
    END
  END wd_in[13]
  PIN wd_in[14]
    DIRECTION INPUT ;
    USE SIGNAL ;
    SHAPE ABUTMENT ;
    PORT
      LAYER metal3 ;
      RECT 0.000 61.005 0.070 61.075 ;
    END
  END wd_in[14]
  PIN wd_in[15]
    DIRECTION INPUT ;
    USE SIGNAL ;
    SHAPE ABUTMENT ;
    PORT
      LAYER metal3 ;
      RECT 0.000 61.425 0.070 61.495 ;
    END
  END wd_in[15]
  PIN wd_in[16]
    DIRECTION INPUT ;
    USE SIGNAL ;
    SHAPE ABUTMENT ;
    PORT
      LAYER metal3 ;
      RECT 0.000 61.845 0.070 61.915 ;
    END
  END wd_in[16]
  PIN wd_in[17]
    DIRECTION INPUT ;
    USE SIGNAL ;
    SHAPE ABUTMENT ;
    PORT
      LAYER metal3 ;
      RECT 0.000 62.265 0.070 62.335 ;
    END
  END wd_in[17]
  PIN wd_in[18]
    DIRECTION INPUT ;
    USE SIGNAL ;
    SHAPE ABUTMENT ;
    PORT
      LAYER metal3 ;
      RECT 0.000 62.685 0.070 62.755 ;
    END
  END wd_in[18]
  PIN wd_in[19]
    DIRECTION INPUT ;
    USE SIGNAL ;
    SHAPE ABUTMENT ;
    PORT
      LAYER metal3 ;
      RECT 0.000 63.105 0.070 63.175 ;
    END
  END wd_in[19]
  PIN wd_in[20]
    DIRECTION INPUT ;
    USE SIGNAL ;
    SHAPE ABUTMENT ;
    PORT
      LAYER metal3 ;
      RECT 0.000 63.525 0.070 63.595 ;
    END
  END wd_in[20]
  PIN wd_in[21]
    DIRECTION INPUT ;
    USE SIGNAL ;
    SHAPE ABUTMENT ;
    PORT
      LAYER metal3 ;
      RECT 0.000 63.945 0.070 64.015 ;
    END
  END wd_in[21]
  PIN wd_in[22]
    DIRECTION INPUT ;
    USE SIGNAL ;
    SHAPE ABUTMENT ;
    PORT
      LAYER metal3 ;
      RECT 0.000 64.365 0.070 64.435 ;
    END
  END wd_in[22]
  PIN wd_in[23]
    DIRECTION INPUT ;
    USE SIGNAL ;
    SHAPE ABUTMENT ;
    PORT
      LAYER metal3 ;
      RECT 0.000 64.785 0.070 64.855 ;
    END
  END wd_in[23]
  PIN wd_in[24]
    DIRECTION INPUT ;
    USE SIGNAL ;
    SHAPE ABUTMENT ;
    PORT
      LAYER metal3 ;
      RECT 0.000 65.205 0.070 65.275 ;
    END
  END wd_in[24]
  PIN wd_in[25]
    DIRECTION INPUT ;
    USE SIGNAL ;
    SHAPE ABUTMENT ;
    PORT
      LAYER metal3 ;
      RECT 0.000 65.625 0.070 65.695 ;
    END
  END wd_in[25]
  PIN wd_in[26]
    DIRECTION INPUT ;
    USE SIGNAL ;
    SHAPE ABUTMENT ;
    PORT
      LAYER metal3 ;
      RECT 0.000 66.045 0.070 66.115 ;
    END
  END wd_in[26]
  PIN wd_in[27]
    DIRECTION INPUT ;
    USE SIGNAL ;
    SHAPE ABUTMENT ;
    PORT
      LAYER metal3 ;
      RECT 0.000 66.465 0.070 66.535 ;
    END
  END wd_in[27]
  PIN wd_in[28]
    DIRECTION INPUT ;
    USE SIGNAL ;
    SHAPE ABUTMENT ;
    PORT
      LAYER metal3 ;
      RECT 0.000 66.885 0.070 66.955 ;
    END
  END wd_in[28]
  PIN wd_in[29]
    DIRECTION INPUT ;
    USE SIGNAL ;
    SHAPE ABUTMENT ;
    PORT
      LAYER metal3 ;
      RECT 0.000 67.305 0.070 67.375 ;
    END
  END wd_in[29]
  PIN wd_in[30]
    DIRECTION INPUT ;
    USE SIGNAL ;
    SHAPE ABUTMENT ;
    PORT
      LAYER metal3 ;
      RECT 0.000 67.725 0.070 67.795 ;
    END
  END wd_in[30]
  PIN wd_in[31]
    DIRECTION INPUT ;
    USE SIGNAL ;
    SHAPE ABUTMENT ;
    PORT
      LAYER metal3 ;
      RECT 0.000 68.145 0.070 68.215 ;
    END
  END wd_in[31]
  PIN wd_in[32]
    DIRECTION INPUT ;
    USE SIGNAL ;
    SHAPE ABUTMENT ;
    PORT
      LAYER metal3 ;
      RECT 0.000 68.565 0.070 68.635 ;
    END
  END wd_in[32]
  PIN wd_in[33]
    DIRECTION INPUT ;
    USE SIGNAL ;
    SHAPE ABUTMENT ;
    PORT
      LAYER metal3 ;
      RECT 0.000 68.985 0.070 69.055 ;
    END
  END wd_in[33]
  PIN wd_in[34]
    DIRECTION INPUT ;
    USE SIGNAL ;
    SHAPE ABUTMENT ;
    PORT
      LAYER metal3 ;
      RECT 0.000 69.405 0.070 69.475 ;
    END
  END wd_in[34]
  PIN wd_in[35]
    DIRECTION INPUT ;
    USE SIGNAL ;
    SHAPE ABUTMENT ;
    PORT
      LAYER metal3 ;
      RECT 0.000 69.825 0.070 69.895 ;
    END
  END wd_in[35]
  PIN wd_in[36]
    DIRECTION INPUT ;
    USE SIGNAL ;
    SHAPE ABUTMENT ;
    PORT
      LAYER metal3 ;
      RECT 0.000 70.245 0.070 70.315 ;
    END
  END wd_in[36]
  PIN wd_in[37]
    DIRECTION INPUT ;
    USE SIGNAL ;
    SHAPE ABUTMENT ;
    PORT
      LAYER metal3 ;
      RECT 0.000 70.665 0.070 70.735 ;
    END
  END wd_in[37]
  PIN wd_in[38]
    DIRECTION INPUT ;
    USE SIGNAL ;
    SHAPE ABUTMENT ;
    PORT
      LAYER metal3 ;
      RECT 0.000 71.085 0.070 71.155 ;
    END
  END wd_in[38]
  PIN wd_in[39]
    DIRECTION INPUT ;
    USE SIGNAL ;
    SHAPE ABUTMENT ;
    PORT
      LAYER metal3 ;
      RECT 0.000 71.505 0.070 71.575 ;
    END
  END wd_in[39]
  PIN wd_in[40]
    DIRECTION INPUT ;
    USE SIGNAL ;
    SHAPE ABUTMENT ;
    PORT
      LAYER metal3 ;
      RECT 0.000 71.925 0.070 71.995 ;
    END
  END wd_in[40]
  PIN wd_in[41]
    DIRECTION INPUT ;
    USE SIGNAL ;
    SHAPE ABUTMENT ;
    PORT
      LAYER metal3 ;
      RECT 0.000 72.345 0.070 72.415 ;
    END
  END wd_in[41]
  PIN wd_in[42]
    DIRECTION INPUT ;
    USE SIGNAL ;
    SHAPE ABUTMENT ;
    PORT
      LAYER metal3 ;
      RECT 0.000 72.765 0.070 72.835 ;
    END
  END wd_in[42]
  PIN wd_in[43]
    DIRECTION INPUT ;
    USE SIGNAL ;
    SHAPE ABUTMENT ;
    PORT
      LAYER metal3 ;
      RECT 0.000 73.185 0.070 73.255 ;
    END
  END wd_in[43]
  PIN wd_in[44]
    DIRECTION INPUT ;
    USE SIGNAL ;
    SHAPE ABUTMENT ;
    PORT
      LAYER metal3 ;
      RECT 0.000 73.605 0.070 73.675 ;
    END
  END wd_in[44]
  PIN wd_in[45]
    DIRECTION INPUT ;
    USE SIGNAL ;
    SHAPE ABUTMENT ;
    PORT
      LAYER metal3 ;
      RECT 0.000 74.025 0.070 74.095 ;
    END
  END wd_in[45]
  PIN wd_in[46]
    DIRECTION INPUT ;
    USE SIGNAL ;
    SHAPE ABUTMENT ;
    PORT
      LAYER metal3 ;
      RECT 0.000 74.445 0.070 74.515 ;
    END
  END wd_in[46]
  PIN wd_in[47]
    DIRECTION INPUT ;
    USE SIGNAL ;
    SHAPE ABUTMENT ;
    PORT
      LAYER metal3 ;
      RECT 0.000 74.865 0.070 74.935 ;
    END
  END wd_in[47]
  PIN wd_in[48]
    DIRECTION INPUT ;
    USE SIGNAL ;
    SHAPE ABUTMENT ;
    PORT
      LAYER metal3 ;
      RECT 0.000 75.285 0.070 75.355 ;
    END
  END wd_in[48]
  PIN wd_in[49]
    DIRECTION INPUT ;
    USE SIGNAL ;
    SHAPE ABUTMENT ;
    PORT
      LAYER metal3 ;
      RECT 0.000 75.705 0.070 75.775 ;
    END
  END wd_in[49]
  PIN wd_in[50]
    DIRECTION INPUT ;
    USE SIGNAL ;
    SHAPE ABUTMENT ;
    PORT
      LAYER metal3 ;
      RECT 0.000 76.125 0.070 76.195 ;
    END
  END wd_in[50]
  PIN wd_in[51]
    DIRECTION INPUT ;
    USE SIGNAL ;
    SHAPE ABUTMENT ;
    PORT
      LAYER metal3 ;
      RECT 0.000 76.545 0.070 76.615 ;
    END
  END wd_in[51]
  PIN wd_in[52]
    DIRECTION INPUT ;
    USE SIGNAL ;
    SHAPE ABUTMENT ;
    PORT
      LAYER metal3 ;
      RECT 0.000 76.965 0.070 77.035 ;
    END
  END wd_in[52]
  PIN wd_in[53]
    DIRECTION INPUT ;
    USE SIGNAL ;
    SHAPE ABUTMENT ;
    PORT
      LAYER metal3 ;
      RECT 0.000 77.385 0.070 77.455 ;
    END
  END wd_in[53]
  PIN wd_in[54]
    DIRECTION INPUT ;
    USE SIGNAL ;
    SHAPE ABUTMENT ;
    PORT
      LAYER metal3 ;
      RECT 0.000 77.805 0.070 77.875 ;
    END
  END wd_in[54]
  PIN wd_in[55]
    DIRECTION INPUT ;
    USE SIGNAL ;
    SHAPE ABUTMENT ;
    PORT
      LAYER metal3 ;
      RECT 0.000 78.225 0.070 78.295 ;
    END
  END wd_in[55]
  PIN wd_in[56]
    DIRECTION INPUT ;
    USE SIGNAL ;
    SHAPE ABUTMENT ;
    PORT
      LAYER metal3 ;
      RECT 0.000 78.645 0.070 78.715 ;
    END
  END wd_in[56]
  PIN wd_in[57]
    DIRECTION INPUT ;
    USE SIGNAL ;
    SHAPE ABUTMENT ;
    PORT
      LAYER metal3 ;
      RECT 0.000 79.065 0.070 79.135 ;
    END
  END wd_in[57]
  PIN wd_in[58]
    DIRECTION INPUT ;
    USE SIGNAL ;
    SHAPE ABUTMENT ;
    PORT
      LAYER metal3 ;
      RECT 0.000 79.485 0.070 79.555 ;
    END
  END wd_in[58]
  PIN wd_in[59]
    DIRECTION INPUT ;
    USE SIGNAL ;
    SHAPE ABUTMENT ;
    PORT
      LAYER metal3 ;
      RECT 0.000 79.905 0.070 79.975 ;
    END
  END wd_in[59]
  PIN wd_in[60]
    DIRECTION INPUT ;
    USE SIGNAL ;
    SHAPE ABUTMENT ;
    PORT
      LAYER metal3 ;
      RECT 0.000 80.325 0.070 80.395 ;
    END
  END wd_in[60]
  PIN wd_in[61]
    DIRECTION INPUT ;
    USE SIGNAL ;
    SHAPE ABUTMENT ;
    PORT
      LAYER metal3 ;
      RECT 0.000 80.745 0.070 80.815 ;
    END
  END wd_in[61]
  PIN wd_in[62]
    DIRECTION INPUT ;
    USE SIGNAL ;
    SHAPE ABUTMENT ;
    PORT
      LAYER metal3 ;
      RECT 0.000 81.165 0.070 81.235 ;
    END
  END wd_in[62]
  PIN wd_in[63]
    DIRECTION INPUT ;
    USE SIGNAL ;
    SHAPE ABUTMENT ;
    PORT
      LAYER metal3 ;
      RECT 0.000 81.585 0.070 81.655 ;
    END
  END wd_in[63]
  PIN wd_in[64]
    DIRECTION INPUT ;
    USE SIGNAL ;
    SHAPE ABUTMENT ;
    PORT
      LAYER metal3 ;
      RECT 0.000 82.005 0.070 82.075 ;
    END
  END wd_in[64]
  PIN wd_in[65]
    DIRECTION INPUT ;
    USE SIGNAL ;
    SHAPE ABUTMENT ;
    PORT
      LAYER metal3 ;
      RECT 0.000 82.425 0.070 82.495 ;
    END
  END wd_in[65]
  PIN wd_in[66]
    DIRECTION INPUT ;
    USE SIGNAL ;
    SHAPE ABUTMENT ;
    PORT
      LAYER metal3 ;
      RECT 0.000 82.845 0.070 82.915 ;
    END
  END wd_in[66]
  PIN wd_in[67]
    DIRECTION INPUT ;
    USE SIGNAL ;
    SHAPE ABUTMENT ;
    PORT
      LAYER metal3 ;
      RECT 0.000 83.265 0.070 83.335 ;
    END
  END wd_in[67]
  PIN wd_in[68]
    DIRECTION INPUT ;
    USE SIGNAL ;
    SHAPE ABUTMENT ;
    PORT
      LAYER metal3 ;
      RECT 0.000 83.685 0.070 83.755 ;
    END
  END wd_in[68]
  PIN wd_in[69]
    DIRECTION INPUT ;
    USE SIGNAL ;
    SHAPE ABUTMENT ;
    PORT
      LAYER metal3 ;
      RECT 0.000 84.105 0.070 84.175 ;
    END
  END wd_in[69]
  PIN wd_in[70]
    DIRECTION INPUT ;
    USE SIGNAL ;
    SHAPE ABUTMENT ;
    PORT
      LAYER metal3 ;
      RECT 0.000 84.525 0.070 84.595 ;
    END
  END wd_in[70]
  PIN wd_in[71]
    DIRECTION INPUT ;
    USE SIGNAL ;
    SHAPE ABUTMENT ;
    PORT
      LAYER metal3 ;
      RECT 0.000 84.945 0.070 85.015 ;
    END
  END wd_in[71]
  PIN wd_in[72]
    DIRECTION INPUT ;
    USE SIGNAL ;
    SHAPE ABUTMENT ;
    PORT
      LAYER metal3 ;
      RECT 0.000 85.365 0.070 85.435 ;
    END
  END wd_in[72]
  PIN wd_in[73]
    DIRECTION INPUT ;
    USE SIGNAL ;
    SHAPE ABUTMENT ;
    PORT
      LAYER metal3 ;
      RECT 0.000 85.785 0.070 85.855 ;
    END
  END wd_in[73]
  PIN wd_in[74]
    DIRECTION INPUT ;
    USE SIGNAL ;
    SHAPE ABUTMENT ;
    PORT
      LAYER metal3 ;
      RECT 0.000 86.205 0.070 86.275 ;
    END
  END wd_in[74]
  PIN wd_in[75]
    DIRECTION INPUT ;
    USE SIGNAL ;
    SHAPE ABUTMENT ;
    PORT
      LAYER metal3 ;
      RECT 0.000 86.625 0.070 86.695 ;
    END
  END wd_in[75]
  PIN wd_in[76]
    DIRECTION INPUT ;
    USE SIGNAL ;
    SHAPE ABUTMENT ;
    PORT
      LAYER metal3 ;
      RECT 0.000 87.045 0.070 87.115 ;
    END
  END wd_in[76]
  PIN wd_in[77]
    DIRECTION INPUT ;
    USE SIGNAL ;
    SHAPE ABUTMENT ;
    PORT
      LAYER metal3 ;
      RECT 0.000 87.465 0.070 87.535 ;
    END
  END wd_in[77]
  PIN wd_in[78]
    DIRECTION INPUT ;
    USE SIGNAL ;
    SHAPE ABUTMENT ;
    PORT
      LAYER metal3 ;
      RECT 0.000 87.885 0.070 87.955 ;
    END
  END wd_in[78]
  PIN wd_in[79]
    DIRECTION INPUT ;
    USE SIGNAL ;
    SHAPE ABUTMENT ;
    PORT
      LAYER metal3 ;
      RECT 0.000 88.305 0.070 88.375 ;
    END
  END wd_in[79]
  PIN wd_in[80]
    DIRECTION INPUT ;
    USE SIGNAL ;
    SHAPE ABUTMENT ;
    PORT
      LAYER metal3 ;
      RECT 0.000 88.725 0.070 88.795 ;
    END
  END wd_in[80]
  PIN wd_in[81]
    DIRECTION INPUT ;
    USE SIGNAL ;
    SHAPE ABUTMENT ;
    PORT
      LAYER metal3 ;
      RECT 0.000 89.145 0.070 89.215 ;
    END
  END wd_in[81]
  PIN wd_in[82]
    DIRECTION INPUT ;
    USE SIGNAL ;
    SHAPE ABUTMENT ;
    PORT
      LAYER metal3 ;
      RECT 0.000 89.565 0.070 89.635 ;
    END
  END wd_in[82]
  PIN wd_in[83]
    DIRECTION INPUT ;
    USE SIGNAL ;
    SHAPE ABUTMENT ;
    PORT
      LAYER metal3 ;
      RECT 0.000 89.985 0.070 90.055 ;
    END
  END wd_in[83]
  PIN wd_in[84]
    DIRECTION INPUT ;
    USE SIGNAL ;
    SHAPE ABUTMENT ;
    PORT
      LAYER metal3 ;
      RECT 0.000 90.405 0.070 90.475 ;
    END
  END wd_in[84]
  PIN wd_in[85]
    DIRECTION INPUT ;
    USE SIGNAL ;
    SHAPE ABUTMENT ;
    PORT
      LAYER metal3 ;
      RECT 0.000 90.825 0.070 90.895 ;
    END
  END wd_in[85]
  PIN wd_in[86]
    DIRECTION INPUT ;
    USE SIGNAL ;
    SHAPE ABUTMENT ;
    PORT
      LAYER metal3 ;
      RECT 0.000 91.245 0.070 91.315 ;
    END
  END wd_in[86]
  PIN wd_in[87]
    DIRECTION INPUT ;
    USE SIGNAL ;
    SHAPE ABUTMENT ;
    PORT
      LAYER metal3 ;
      RECT 0.000 91.665 0.070 91.735 ;
    END
  END wd_in[87]
  PIN wd_in[88]
    DIRECTION INPUT ;
    USE SIGNAL ;
    SHAPE ABUTMENT ;
    PORT
      LAYER metal3 ;
      RECT 0.000 92.085 0.070 92.155 ;
    END
  END wd_in[88]
  PIN wd_in[89]
    DIRECTION INPUT ;
    USE SIGNAL ;
    SHAPE ABUTMENT ;
    PORT
      LAYER metal3 ;
      RECT 0.000 92.505 0.070 92.575 ;
    END
  END wd_in[89]
  PIN wd_in[90]
    DIRECTION INPUT ;
    USE SIGNAL ;
    SHAPE ABUTMENT ;
    PORT
      LAYER metal3 ;
      RECT 0.000 92.925 0.070 92.995 ;
    END
  END wd_in[90]
  PIN wd_in[91]
    DIRECTION INPUT ;
    USE SIGNAL ;
    SHAPE ABUTMENT ;
    PORT
      LAYER metal3 ;
      RECT 0.000 93.345 0.070 93.415 ;
    END
  END wd_in[91]
  PIN wd_in[92]
    DIRECTION INPUT ;
    USE SIGNAL ;
    SHAPE ABUTMENT ;
    PORT
      LAYER metal3 ;
      RECT 0.000 93.765 0.070 93.835 ;
    END
  END wd_in[92]
  PIN wd_in[93]
    DIRECTION INPUT ;
    USE SIGNAL ;
    SHAPE ABUTMENT ;
    PORT
      LAYER metal3 ;
      RECT 0.000 94.185 0.070 94.255 ;
    END
  END wd_in[93]
  PIN wd_in[94]
    DIRECTION INPUT ;
    USE SIGNAL ;
    SHAPE ABUTMENT ;
    PORT
      LAYER metal3 ;
      RECT 0.000 94.605 0.070 94.675 ;
    END
  END wd_in[94]
  PIN wd_in[95]
    DIRECTION INPUT ;
    USE SIGNAL ;
    SHAPE ABUTMENT ;
    PORT
      LAYER metal3 ;
      RECT 0.000 95.025 0.070 95.095 ;
    END
  END wd_in[95]
  PIN wd_in[96]
    DIRECTION INPUT ;
    USE SIGNAL ;
    SHAPE ABUTMENT ;
    PORT
      LAYER metal3 ;
      RECT 0.000 95.445 0.070 95.515 ;
    END
  END wd_in[96]
  PIN wd_in[97]
    DIRECTION INPUT ;
    USE SIGNAL ;
    SHAPE ABUTMENT ;
    PORT
      LAYER metal3 ;
      RECT 0.000 95.865 0.070 95.935 ;
    END
  END wd_in[97]
  PIN wd_in[98]
    DIRECTION INPUT ;
    USE SIGNAL ;
    SHAPE ABUTMENT ;
    PORT
      LAYER metal3 ;
      RECT 0.000 96.285 0.070 96.355 ;
    END
  END wd_in[98]
  PIN wd_in[99]
    DIRECTION INPUT ;
    USE SIGNAL ;
    SHAPE ABUTMENT ;
    PORT
      LAYER metal3 ;
      RECT 0.000 96.705 0.070 96.775 ;
    END
  END wd_in[99]
  PIN wd_in[100]
    DIRECTION INPUT ;
    USE SIGNAL ;
    SHAPE ABUTMENT ;
    PORT
      LAYER metal3 ;
      RECT 0.000 97.125 0.070 97.195 ;
    END
  END wd_in[100]
  PIN wd_in[101]
    DIRECTION INPUT ;
    USE SIGNAL ;
    SHAPE ABUTMENT ;
    PORT
      LAYER metal3 ;
      RECT 0.000 97.545 0.070 97.615 ;
    END
  END wd_in[101]
  PIN wd_in[102]
    DIRECTION INPUT ;
    USE SIGNAL ;
    SHAPE ABUTMENT ;
    PORT
      LAYER metal3 ;
      RECT 0.000 97.965 0.070 98.035 ;
    END
  END wd_in[102]
  PIN wd_in[103]
    DIRECTION INPUT ;
    USE SIGNAL ;
    SHAPE ABUTMENT ;
    PORT
      LAYER metal3 ;
      RECT 0.000 98.385 0.070 98.455 ;
    END
  END wd_in[103]
  PIN wd_in[104]
    DIRECTION INPUT ;
    USE SIGNAL ;
    SHAPE ABUTMENT ;
    PORT
      LAYER metal3 ;
      RECT 0.000 98.805 0.070 98.875 ;
    END
  END wd_in[104]
  PIN wd_in[105]
    DIRECTION INPUT ;
    USE SIGNAL ;
    SHAPE ABUTMENT ;
    PORT
      LAYER metal3 ;
      RECT 0.000 99.225 0.070 99.295 ;
    END
  END wd_in[105]
  PIN wd_in[106]
    DIRECTION INPUT ;
    USE SIGNAL ;
    SHAPE ABUTMENT ;
    PORT
      LAYER metal3 ;
      RECT 0.000 99.645 0.070 99.715 ;
    END
  END wd_in[106]
  PIN wd_in[107]
    DIRECTION INPUT ;
    USE SIGNAL ;
    SHAPE ABUTMENT ;
    PORT
      LAYER metal3 ;
      RECT 0.000 100.065 0.070 100.135 ;
    END
  END wd_in[107]
  PIN wd_in[108]
    DIRECTION INPUT ;
    USE SIGNAL ;
    SHAPE ABUTMENT ;
    PORT
      LAYER metal3 ;
      RECT 0.000 100.485 0.070 100.555 ;
    END
  END wd_in[108]
  PIN wd_in[109]
    DIRECTION INPUT ;
    USE SIGNAL ;
    SHAPE ABUTMENT ;
    PORT
      LAYER metal3 ;
      RECT 0.000 100.905 0.070 100.975 ;
    END
  END wd_in[109]
  PIN wd_in[110]
    DIRECTION INPUT ;
    USE SIGNAL ;
    SHAPE ABUTMENT ;
    PORT
      LAYER metal3 ;
      RECT 0.000 101.325 0.070 101.395 ;
    END
  END wd_in[110]
  PIN wd_in[111]
    DIRECTION INPUT ;
    USE SIGNAL ;
    SHAPE ABUTMENT ;
    PORT
      LAYER metal3 ;
      RECT 0.000 101.745 0.070 101.815 ;
    END
  END wd_in[111]
  PIN wd_in[112]
    DIRECTION INPUT ;
    USE SIGNAL ;
    SHAPE ABUTMENT ;
    PORT
      LAYER metal3 ;
      RECT 0.000 102.165 0.070 102.235 ;
    END
  END wd_in[112]
  PIN wd_in[113]
    DIRECTION INPUT ;
    USE SIGNAL ;
    SHAPE ABUTMENT ;
    PORT
      LAYER metal3 ;
      RECT 0.000 102.585 0.070 102.655 ;
    END
  END wd_in[113]
  PIN wd_in[114]
    DIRECTION INPUT ;
    USE SIGNAL ;
    SHAPE ABUTMENT ;
    PORT
      LAYER metal3 ;
      RECT 0.000 103.005 0.070 103.075 ;
    END
  END wd_in[114]
  PIN wd_in[115]
    DIRECTION INPUT ;
    USE SIGNAL ;
    SHAPE ABUTMENT ;
    PORT
      LAYER metal3 ;
      RECT 0.000 103.425 0.070 103.495 ;
    END
  END wd_in[115]
  PIN wd_in[116]
    DIRECTION INPUT ;
    USE SIGNAL ;
    SHAPE ABUTMENT ;
    PORT
      LAYER metal3 ;
      RECT 0.000 103.845 0.070 103.915 ;
    END
  END wd_in[116]
  PIN wd_in[117]
    DIRECTION INPUT ;
    USE SIGNAL ;
    SHAPE ABUTMENT ;
    PORT
      LAYER metal3 ;
      RECT 0.000 104.265 0.070 104.335 ;
    END
  END wd_in[117]
  PIN wd_in[118]
    DIRECTION INPUT ;
    USE SIGNAL ;
    SHAPE ABUTMENT ;
    PORT
      LAYER metal3 ;
      RECT 0.000 104.685 0.070 104.755 ;
    END
  END wd_in[118]
  PIN wd_in[119]
    DIRECTION INPUT ;
    USE SIGNAL ;
    SHAPE ABUTMENT ;
    PORT
      LAYER metal3 ;
      RECT 0.000 105.105 0.070 105.175 ;
    END
  END wd_in[119]
  PIN wd_in[120]
    DIRECTION INPUT ;
    USE SIGNAL ;
    SHAPE ABUTMENT ;
    PORT
      LAYER metal3 ;
      RECT 0.000 105.525 0.070 105.595 ;
    END
  END wd_in[120]
  PIN wd_in[121]
    DIRECTION INPUT ;
    USE SIGNAL ;
    SHAPE ABUTMENT ;
    PORT
      LAYER metal3 ;
      RECT 0.000 105.945 0.070 106.015 ;
    END
  END wd_in[121]
  PIN wd_in[122]
    DIRECTION INPUT ;
    USE SIGNAL ;
    SHAPE ABUTMENT ;
    PORT
      LAYER metal3 ;
      RECT 0.000 106.365 0.070 106.435 ;
    END
  END wd_in[122]
  PIN wd_in[123]
    DIRECTION INPUT ;
    USE SIGNAL ;
    SHAPE ABUTMENT ;
    PORT
      LAYER metal3 ;
      RECT 0.000 106.785 0.070 106.855 ;
    END
  END wd_in[123]
  PIN wd_in[124]
    DIRECTION INPUT ;
    USE SIGNAL ;
    SHAPE ABUTMENT ;
    PORT
      LAYER metal3 ;
      RECT 0.000 107.205 0.070 107.275 ;
    END
  END wd_in[124]
  PIN wd_in[125]
    DIRECTION INPUT ;
    USE SIGNAL ;
    SHAPE ABUTMENT ;
    PORT
      LAYER metal3 ;
      RECT 0.000 107.625 0.070 107.695 ;
    END
  END wd_in[125]
  PIN wd_in[126]
    DIRECTION INPUT ;
    USE SIGNAL ;
    SHAPE ABUTMENT ;
    PORT
      LAYER metal3 ;
      RECT 0.000 108.045 0.070 108.115 ;
    END
  END wd_in[126]
  PIN wd_in[127]
    DIRECTION INPUT ;
    USE SIGNAL ;
    SHAPE ABUTMENT ;
    PORT
      LAYER metal3 ;
      RECT 0.000 108.465 0.070 108.535 ;
    END
  END wd_in[127]
  PIN w_addr_in[0]
    DIRECTION INPUT ;
    USE SIGNAL ;
    SHAPE ABUTMENT ;
    PORT
      LAYER metal3 ;
      RECT 0.000 108.885 0.070 108.955 ;
    END
  END w_addr_in[0]
  PIN w_addr_in[1]
    DIRECTION INPUT ;
    USE SIGNAL ;
    SHAPE ABUTMENT ;
    PORT
      LAYER metal3 ;
      RECT 0.000 109.305 0.070 109.375 ;
    END
  END w_addr_in[1]
  PIN w_addr_in[2]
    DIRECTION INPUT ;
    USE SIGNAL ;
    SHAPE ABUTMENT ;
    PORT
      LAYER metal3 ;
      RECT 0.000 109.725 0.070 109.795 ;
    END
  END w_addr_in[2]
  PIN w_addr_in[3]
    DIRECTION INPUT ;
    USE SIGNAL ;
    SHAPE ABUTMENT ;
    PORT
      LAYER metal3 ;
      RECT 0.000 110.145 0.070 110.215 ;
    END
  END w_addr_in[3]
  PIN w_addr_in[4]
    DIRECTION INPUT ;
    USE SIGNAL ;
    SHAPE ABUTMENT ;
    PORT
      LAYER metal3 ;
      RECT 0.000 110.565 0.070 110.635 ;
    END
  END w_addr_in[4]
  PIN w_addr_in[5]
    DIRECTION INPUT ;
    USE SIGNAL ;
    SHAPE ABUTMENT ;
    PORT
      LAYER metal3 ;
      RECT 0.000 110.985 0.070 111.055 ;
    END
  END w_addr_in[5]
  PIN w_ce_in
    DIRECTION INPUT ;
    USE SIGNAL ;
    SHAPE ABUTMENT ;
    PORT
      LAYER metal3 ;
      RECT 0.000 111.405 0.070 111.475 ;
    END
  END w_ce_in
  PIN rd_out[0]
    DIRECTION OUTPUT ;
    USE SIGNAL ;
    SHAPE ABUTMENT ;
    PORT
      LAYER metal3 ;
      RECT 0.000 115.465 0.070 115.535 ;
    END
  END rd_out[0]
  PIN rd_out[1]
    DIRECTION OUTPUT ;
    USE SIGNAL ;
    SHAPE ABUTMENT ;
    PORT
      LAYER metal3 ;
      RECT 0.000 115.885 0.070 115.955 ;
    END
  END rd_out[1]
  PIN rd_out[2]
    DIRECTION OUTPUT ;
    USE SIGNAL ;
    SHAPE ABUTMENT ;
    PORT
      LAYER metal3 ;
      RECT 0.000 116.305 0.070 116.375 ;
    END
  END rd_out[2]
  PIN rd_out[3]
    DIRECTION OUTPUT ;
    USE SIGNAL ;
    SHAPE ABUTMENT ;
    PORT
      LAYER metal3 ;
      RECT 0.000 116.725 0.070 116.795 ;
    END
  END rd_out[3]
  PIN rd_out[4]
    DIRECTION OUTPUT ;
    USE SIGNAL ;
    SHAPE ABUTMENT ;
    PORT
      LAYER metal3 ;
      RECT 0.000 117.145 0.070 117.215 ;
    END
  END rd_out[4]
  PIN rd_out[5]
    DIRECTION OUTPUT ;
    USE SIGNAL ;
    SHAPE ABUTMENT ;
    PORT
      LAYER metal3 ;
      RECT 0.000 117.565 0.070 117.635 ;
    END
  END rd_out[5]
  PIN rd_out[6]
    DIRECTION OUTPUT ;
    USE SIGNAL ;
    SHAPE ABUTMENT ;
    PORT
      LAYER metal3 ;
      RECT 0.000 117.985 0.070 118.055 ;
    END
  END rd_out[6]
  PIN rd_out[7]
    DIRECTION OUTPUT ;
    USE SIGNAL ;
    SHAPE ABUTMENT ;
    PORT
      LAYER metal3 ;
      RECT 0.000 118.405 0.070 118.475 ;
    END
  END rd_out[7]
  PIN rd_out[8]
    DIRECTION OUTPUT ;
    USE SIGNAL ;
    SHAPE ABUTMENT ;
    PORT
      LAYER metal3 ;
      RECT 0.000 118.825 0.070 118.895 ;
    END
  END rd_out[8]
  PIN rd_out[9]
    DIRECTION OUTPUT ;
    USE SIGNAL ;
    SHAPE ABUTMENT ;
    PORT
      LAYER metal3 ;
      RECT 0.000 119.245 0.070 119.315 ;
    END
  END rd_out[9]
  PIN rd_out[10]
    DIRECTION OUTPUT ;
    USE SIGNAL ;
    SHAPE ABUTMENT ;
    PORT
      LAYER metal3 ;
      RECT 0.000 119.665 0.070 119.735 ;
    END
  END rd_out[10]
  PIN rd_out[11]
    DIRECTION OUTPUT ;
    USE SIGNAL ;
    SHAPE ABUTMENT ;
    PORT
      LAYER metal3 ;
      RECT 0.000 120.085 0.070 120.155 ;
    END
  END rd_out[11]
  PIN rd_out[12]
    DIRECTION OUTPUT ;
    USE SIGNAL ;
    SHAPE ABUTMENT ;
    PORT
      LAYER metal3 ;
      RECT 0.000 120.505 0.070 120.575 ;
    END
  END rd_out[12]
  PIN rd_out[13]
    DIRECTION OUTPUT ;
    USE SIGNAL ;
    SHAPE ABUTMENT ;
    PORT
      LAYER metal3 ;
      RECT 0.000 120.925 0.070 120.995 ;
    END
  END rd_out[13]
  PIN rd_out[14]
    DIRECTION OUTPUT ;
    USE SIGNAL ;
    SHAPE ABUTMENT ;
    PORT
      LAYER metal3 ;
      RECT 0.000 121.345 0.070 121.415 ;
    END
  END rd_out[14]
  PIN rd_out[15]
    DIRECTION OUTPUT ;
    USE SIGNAL ;
    SHAPE ABUTMENT ;
    PORT
      LAYER metal3 ;
      RECT 0.000 121.765 0.070 121.835 ;
    END
  END rd_out[15]
  PIN rd_out[16]
    DIRECTION OUTPUT ;
    USE SIGNAL ;
    SHAPE ABUTMENT ;
    PORT
      LAYER metal3 ;
      RECT 0.000 122.185 0.070 122.255 ;
    END
  END rd_out[16]
  PIN rd_out[17]
    DIRECTION OUTPUT ;
    USE SIGNAL ;
    SHAPE ABUTMENT ;
    PORT
      LAYER metal3 ;
      RECT 0.000 122.605 0.070 122.675 ;
    END
  END rd_out[17]
  PIN rd_out[18]
    DIRECTION OUTPUT ;
    USE SIGNAL ;
    SHAPE ABUTMENT ;
    PORT
      LAYER metal3 ;
      RECT 0.000 123.025 0.070 123.095 ;
    END
  END rd_out[18]
  PIN rd_out[19]
    DIRECTION OUTPUT ;
    USE SIGNAL ;
    SHAPE ABUTMENT ;
    PORT
      LAYER metal3 ;
      RECT 0.000 123.445 0.070 123.515 ;
    END
  END rd_out[19]
  PIN rd_out[20]
    DIRECTION OUTPUT ;
    USE SIGNAL ;
    SHAPE ABUTMENT ;
    PORT
      LAYER metal3 ;
      RECT 0.000 123.865 0.070 123.935 ;
    END
  END rd_out[20]
  PIN rd_out[21]
    DIRECTION OUTPUT ;
    USE SIGNAL ;
    SHAPE ABUTMENT ;
    PORT
      LAYER metal3 ;
      RECT 0.000 124.285 0.070 124.355 ;
    END
  END rd_out[21]
  PIN rd_out[22]
    DIRECTION OUTPUT ;
    USE SIGNAL ;
    SHAPE ABUTMENT ;
    PORT
      LAYER metal3 ;
      RECT 0.000 124.705 0.070 124.775 ;
    END
  END rd_out[22]
  PIN rd_out[23]
    DIRECTION OUTPUT ;
    USE SIGNAL ;
    SHAPE ABUTMENT ;
    PORT
      LAYER metal3 ;
      RECT 0.000 125.125 0.070 125.195 ;
    END
  END rd_out[23]
  PIN rd_out[24]
    DIRECTION OUTPUT ;
    USE SIGNAL ;
    SHAPE ABUTMENT ;
    PORT
      LAYER metal3 ;
      RECT 0.000 125.545 0.070 125.615 ;
    END
  END rd_out[24]
  PIN rd_out[25]
    DIRECTION OUTPUT ;
    USE SIGNAL ;
    SHAPE ABUTMENT ;
    PORT
      LAYER metal3 ;
      RECT 0.000 125.965 0.070 126.035 ;
    END
  END rd_out[25]
  PIN rd_out[26]
    DIRECTION OUTPUT ;
    USE SIGNAL ;
    SHAPE ABUTMENT ;
    PORT
      LAYER metal3 ;
      RECT 0.000 126.385 0.070 126.455 ;
    END
  END rd_out[26]
  PIN rd_out[27]
    DIRECTION OUTPUT ;
    USE SIGNAL ;
    SHAPE ABUTMENT ;
    PORT
      LAYER metal3 ;
      RECT 0.000 126.805 0.070 126.875 ;
    END
  END rd_out[27]
  PIN rd_out[28]
    DIRECTION OUTPUT ;
    USE SIGNAL ;
    SHAPE ABUTMENT ;
    PORT
      LAYER metal3 ;
      RECT 0.000 127.225 0.070 127.295 ;
    END
  END rd_out[28]
  PIN rd_out[29]
    DIRECTION OUTPUT ;
    USE SIGNAL ;
    SHAPE ABUTMENT ;
    PORT
      LAYER metal3 ;
      RECT 0.000 127.645 0.070 127.715 ;
    END
  END rd_out[29]
  PIN rd_out[30]
    DIRECTION OUTPUT ;
    USE SIGNAL ;
    SHAPE ABUTMENT ;
    PORT
      LAYER metal3 ;
      RECT 0.000 128.065 0.070 128.135 ;
    END
  END rd_out[30]
  PIN rd_out[31]
    DIRECTION OUTPUT ;
    USE SIGNAL ;
    SHAPE ABUTMENT ;
    PORT
      LAYER metal3 ;
      RECT 0.000 128.485 0.070 128.555 ;
    END
  END rd_out[31]
  PIN rd_out[32]
    DIRECTION OUTPUT ;
    USE SIGNAL ;
    SHAPE ABUTMENT ;
    PORT
      LAYER metal3 ;
      RECT 0.000 128.905 0.070 128.975 ;
    END
  END rd_out[32]
  PIN rd_out[33]
    DIRECTION OUTPUT ;
    USE SIGNAL ;
    SHAPE ABUTMENT ;
    PORT
      LAYER metal3 ;
      RECT 0.000 129.325 0.070 129.395 ;
    END
  END rd_out[33]
  PIN rd_out[34]
    DIRECTION OUTPUT ;
    USE SIGNAL ;
    SHAPE ABUTMENT ;
    PORT
      LAYER metal3 ;
      RECT 0.000 129.745 0.070 129.815 ;
    END
  END rd_out[34]
  PIN rd_out[35]
    DIRECTION OUTPUT ;
    USE SIGNAL ;
    SHAPE ABUTMENT ;
    PORT
      LAYER metal3 ;
      RECT 0.000 130.165 0.070 130.235 ;
    END
  END rd_out[35]
  PIN rd_out[36]
    DIRECTION OUTPUT ;
    USE SIGNAL ;
    SHAPE ABUTMENT ;
    PORT
      LAYER metal3 ;
      RECT 0.000 130.585 0.070 130.655 ;
    END
  END rd_out[36]
  PIN rd_out[37]
    DIRECTION OUTPUT ;
    USE SIGNAL ;
    SHAPE ABUTMENT ;
    PORT
      LAYER metal3 ;
      RECT 0.000 131.005 0.070 131.075 ;
    END
  END rd_out[37]
  PIN rd_out[38]
    DIRECTION OUTPUT ;
    USE SIGNAL ;
    SHAPE ABUTMENT ;
    PORT
      LAYER metal3 ;
      RECT 0.000 131.425 0.070 131.495 ;
    END
  END rd_out[38]
  PIN rd_out[39]
    DIRECTION OUTPUT ;
    USE SIGNAL ;
    SHAPE ABUTMENT ;
    PORT
      LAYER metal3 ;
      RECT 0.000 131.845 0.070 131.915 ;
    END
  END rd_out[39]
  PIN rd_out[40]
    DIRECTION OUTPUT ;
    USE SIGNAL ;
    SHAPE ABUTMENT ;
    PORT
      LAYER metal3 ;
      RECT 0.000 132.265 0.070 132.335 ;
    END
  END rd_out[40]
  PIN rd_out[41]
    DIRECTION OUTPUT ;
    USE SIGNAL ;
    SHAPE ABUTMENT ;
    PORT
      LAYER metal3 ;
      RECT 0.000 132.685 0.070 132.755 ;
    END
  END rd_out[41]
  PIN rd_out[42]
    DIRECTION OUTPUT ;
    USE SIGNAL ;
    SHAPE ABUTMENT ;
    PORT
      LAYER metal3 ;
      RECT 0.000 133.105 0.070 133.175 ;
    END
  END rd_out[42]
  PIN rd_out[43]
    DIRECTION OUTPUT ;
    USE SIGNAL ;
    SHAPE ABUTMENT ;
    PORT
      LAYER metal3 ;
      RECT 0.000 133.525 0.070 133.595 ;
    END
  END rd_out[43]
  PIN rd_out[44]
    DIRECTION OUTPUT ;
    USE SIGNAL ;
    SHAPE ABUTMENT ;
    PORT
      LAYER metal3 ;
      RECT 0.000 133.945 0.070 134.015 ;
    END
  END rd_out[44]
  PIN rd_out[45]
    DIRECTION OUTPUT ;
    USE SIGNAL ;
    SHAPE ABUTMENT ;
    PORT
      LAYER metal3 ;
      RECT 0.000 134.365 0.070 134.435 ;
    END
  END rd_out[45]
  PIN rd_out[46]
    DIRECTION OUTPUT ;
    USE SIGNAL ;
    SHAPE ABUTMENT ;
    PORT
      LAYER metal3 ;
      RECT 0.000 134.785 0.070 134.855 ;
    END
  END rd_out[46]
  PIN rd_out[47]
    DIRECTION OUTPUT ;
    USE SIGNAL ;
    SHAPE ABUTMENT ;
    PORT
      LAYER metal3 ;
      RECT 0.000 135.205 0.070 135.275 ;
    END
  END rd_out[47]
  PIN rd_out[48]
    DIRECTION OUTPUT ;
    USE SIGNAL ;
    SHAPE ABUTMENT ;
    PORT
      LAYER metal3 ;
      RECT 0.000 135.625 0.070 135.695 ;
    END
  END rd_out[48]
  PIN rd_out[49]
    DIRECTION OUTPUT ;
    USE SIGNAL ;
    SHAPE ABUTMENT ;
    PORT
      LAYER metal3 ;
      RECT 0.000 136.045 0.070 136.115 ;
    END
  END rd_out[49]
  PIN rd_out[50]
    DIRECTION OUTPUT ;
    USE SIGNAL ;
    SHAPE ABUTMENT ;
    PORT
      LAYER metal3 ;
      RECT 0.000 136.465 0.070 136.535 ;
    END
  END rd_out[50]
  PIN rd_out[51]
    DIRECTION OUTPUT ;
    USE SIGNAL ;
    SHAPE ABUTMENT ;
    PORT
      LAYER metal3 ;
      RECT 0.000 136.885 0.070 136.955 ;
    END
  END rd_out[51]
  PIN rd_out[52]
    DIRECTION OUTPUT ;
    USE SIGNAL ;
    SHAPE ABUTMENT ;
    PORT
      LAYER metal3 ;
      RECT 0.000 137.305 0.070 137.375 ;
    END
  END rd_out[52]
  PIN rd_out[53]
    DIRECTION OUTPUT ;
    USE SIGNAL ;
    SHAPE ABUTMENT ;
    PORT
      LAYER metal3 ;
      RECT 0.000 137.725 0.070 137.795 ;
    END
  END rd_out[53]
  PIN rd_out[54]
    DIRECTION OUTPUT ;
    USE SIGNAL ;
    SHAPE ABUTMENT ;
    PORT
      LAYER metal3 ;
      RECT 0.000 138.145 0.070 138.215 ;
    END
  END rd_out[54]
  PIN rd_out[55]
    DIRECTION OUTPUT ;
    USE SIGNAL ;
    SHAPE ABUTMENT ;
    PORT
      LAYER metal3 ;
      RECT 0.000 138.565 0.070 138.635 ;
    END
  END rd_out[55]
  PIN rd_out[56]
    DIRECTION OUTPUT ;
    USE SIGNAL ;
    SHAPE ABUTMENT ;
    PORT
      LAYER metal3 ;
      RECT 0.000 138.985 0.070 139.055 ;
    END
  END rd_out[56]
  PIN rd_out[57]
    DIRECTION OUTPUT ;
    USE SIGNAL ;
    SHAPE ABUTMENT ;
    PORT
      LAYER metal3 ;
      RECT 0.000 139.405 0.070 139.475 ;
    END
  END rd_out[57]
  PIN rd_out[58]
    DIRECTION OUTPUT ;
    USE SIGNAL ;
    SHAPE ABUTMENT ;
    PORT
      LAYER metal3 ;
      RECT 0.000 139.825 0.070 139.895 ;
    END
  END rd_out[58]
  PIN rd_out[59]
    DIRECTION OUTPUT ;
    USE SIGNAL ;
    SHAPE ABUTMENT ;
    PORT
      LAYER metal3 ;
      RECT 0.000 140.245 0.070 140.315 ;
    END
  END rd_out[59]
  PIN rd_out[60]
    DIRECTION OUTPUT ;
    USE SIGNAL ;
    SHAPE ABUTMENT ;
    PORT
      LAYER metal3 ;
      RECT 0.000 140.665 0.070 140.735 ;
    END
  END rd_out[60]
  PIN rd_out[61]
    DIRECTION OUTPUT ;
    USE SIGNAL ;
    SHAPE ABUTMENT ;
    PORT
      LAYER metal3 ;
      RECT 0.000 141.085 0.070 141.155 ;
    END
  END rd_out[61]
  PIN rd_out[62]
    DIRECTION OUTPUT ;
    USE SIGNAL ;
    SHAPE ABUTMENT ;
    PORT
      LAYER metal3 ;
      RECT 0.000 141.505 0.070 141.575 ;
    END
  END rd_out[62]
  PIN rd_out[63]
    DIRECTION OUTPUT ;
    USE SIGNAL ;
    SHAPE ABUTMENT ;
    PORT
      LAYER metal3 ;
      RECT 0.000 141.925 0.070 141.995 ;
    END
  END rd_out[63]
  PIN rd_out[64]
    DIRECTION OUTPUT ;
    USE SIGNAL ;
    SHAPE ABUTMENT ;
    PORT
      LAYER metal3 ;
      RECT 0.000 142.345 0.070 142.415 ;
    END
  END rd_out[64]
  PIN rd_out[65]
    DIRECTION OUTPUT ;
    USE SIGNAL ;
    SHAPE ABUTMENT ;
    PORT
      LAYER metal3 ;
      RECT 0.000 142.765 0.070 142.835 ;
    END
  END rd_out[65]
  PIN rd_out[66]
    DIRECTION OUTPUT ;
    USE SIGNAL ;
    SHAPE ABUTMENT ;
    PORT
      LAYER metal3 ;
      RECT 0.000 143.185 0.070 143.255 ;
    END
  END rd_out[66]
  PIN rd_out[67]
    DIRECTION OUTPUT ;
    USE SIGNAL ;
    SHAPE ABUTMENT ;
    PORT
      LAYER metal3 ;
      RECT 0.000 143.605 0.070 143.675 ;
    END
  END rd_out[67]
  PIN rd_out[68]
    DIRECTION OUTPUT ;
    USE SIGNAL ;
    SHAPE ABUTMENT ;
    PORT
      LAYER metal3 ;
      RECT 0.000 144.025 0.070 144.095 ;
    END
  END rd_out[68]
  PIN rd_out[69]
    DIRECTION OUTPUT ;
    USE SIGNAL ;
    SHAPE ABUTMENT ;
    PORT
      LAYER metal3 ;
      RECT 0.000 144.445 0.070 144.515 ;
    END
  END rd_out[69]
  PIN rd_out[70]
    DIRECTION OUTPUT ;
    USE SIGNAL ;
    SHAPE ABUTMENT ;
    PORT
      LAYER metal3 ;
      RECT 0.000 144.865 0.070 144.935 ;
    END
  END rd_out[70]
  PIN rd_out[71]
    DIRECTION OUTPUT ;
    USE SIGNAL ;
    SHAPE ABUTMENT ;
    PORT
      LAYER metal3 ;
      RECT 0.000 145.285 0.070 145.355 ;
    END
  END rd_out[71]
  PIN rd_out[72]
    DIRECTION OUTPUT ;
    USE SIGNAL ;
    SHAPE ABUTMENT ;
    PORT
      LAYER metal3 ;
      RECT 0.000 145.705 0.070 145.775 ;
    END
  END rd_out[72]
  PIN rd_out[73]
    DIRECTION OUTPUT ;
    USE SIGNAL ;
    SHAPE ABUTMENT ;
    PORT
      LAYER metal3 ;
      RECT 0.000 146.125 0.070 146.195 ;
    END
  END rd_out[73]
  PIN rd_out[74]
    DIRECTION OUTPUT ;
    USE SIGNAL ;
    SHAPE ABUTMENT ;
    PORT
      LAYER metal3 ;
      RECT 0.000 146.545 0.070 146.615 ;
    END
  END rd_out[74]
  PIN rd_out[75]
    DIRECTION OUTPUT ;
    USE SIGNAL ;
    SHAPE ABUTMENT ;
    PORT
      LAYER metal3 ;
      RECT 0.000 146.965 0.070 147.035 ;
    END
  END rd_out[75]
  PIN rd_out[76]
    DIRECTION OUTPUT ;
    USE SIGNAL ;
    SHAPE ABUTMENT ;
    PORT
      LAYER metal3 ;
      RECT 0.000 147.385 0.070 147.455 ;
    END
  END rd_out[76]
  PIN rd_out[77]
    DIRECTION OUTPUT ;
    USE SIGNAL ;
    SHAPE ABUTMENT ;
    PORT
      LAYER metal3 ;
      RECT 0.000 147.805 0.070 147.875 ;
    END
  END rd_out[77]
  PIN rd_out[78]
    DIRECTION OUTPUT ;
    USE SIGNAL ;
    SHAPE ABUTMENT ;
    PORT
      LAYER metal3 ;
      RECT 0.000 148.225 0.070 148.295 ;
    END
  END rd_out[78]
  PIN rd_out[79]
    DIRECTION OUTPUT ;
    USE SIGNAL ;
    SHAPE ABUTMENT ;
    PORT
      LAYER metal3 ;
      RECT 0.000 148.645 0.070 148.715 ;
    END
  END rd_out[79]
  PIN rd_out[80]
    DIRECTION OUTPUT ;
    USE SIGNAL ;
    SHAPE ABUTMENT ;
    PORT
      LAYER metal3 ;
      RECT 0.000 149.065 0.070 149.135 ;
    END
  END rd_out[80]
  PIN rd_out[81]
    DIRECTION OUTPUT ;
    USE SIGNAL ;
    SHAPE ABUTMENT ;
    PORT
      LAYER metal3 ;
      RECT 0.000 149.485 0.070 149.555 ;
    END
  END rd_out[81]
  PIN rd_out[82]
    DIRECTION OUTPUT ;
    USE SIGNAL ;
    SHAPE ABUTMENT ;
    PORT
      LAYER metal3 ;
      RECT 0.000 149.905 0.070 149.975 ;
    END
  END rd_out[82]
  PIN rd_out[83]
    DIRECTION OUTPUT ;
    USE SIGNAL ;
    SHAPE ABUTMENT ;
    PORT
      LAYER metal3 ;
      RECT 0.000 150.325 0.070 150.395 ;
    END
  END rd_out[83]
  PIN rd_out[84]
    DIRECTION OUTPUT ;
    USE SIGNAL ;
    SHAPE ABUTMENT ;
    PORT
      LAYER metal3 ;
      RECT 0.000 150.745 0.070 150.815 ;
    END
  END rd_out[84]
  PIN rd_out[85]
    DIRECTION OUTPUT ;
    USE SIGNAL ;
    SHAPE ABUTMENT ;
    PORT
      LAYER metal3 ;
      RECT 0.000 151.165 0.070 151.235 ;
    END
  END rd_out[85]
  PIN rd_out[86]
    DIRECTION OUTPUT ;
    USE SIGNAL ;
    SHAPE ABUTMENT ;
    PORT
      LAYER metal3 ;
      RECT 0.000 151.585 0.070 151.655 ;
    END
  END rd_out[86]
  PIN rd_out[87]
    DIRECTION OUTPUT ;
    USE SIGNAL ;
    SHAPE ABUTMENT ;
    PORT
      LAYER metal3 ;
      RECT 0.000 152.005 0.070 152.075 ;
    END
  END rd_out[87]
  PIN rd_out[88]
    DIRECTION OUTPUT ;
    USE SIGNAL ;
    SHAPE ABUTMENT ;
    PORT
      LAYER metal3 ;
      RECT 0.000 152.425 0.070 152.495 ;
    END
  END rd_out[88]
  PIN rd_out[89]
    DIRECTION OUTPUT ;
    USE SIGNAL ;
    SHAPE ABUTMENT ;
    PORT
      LAYER metal3 ;
      RECT 0.000 152.845 0.070 152.915 ;
    END
  END rd_out[89]
  PIN rd_out[90]
    DIRECTION OUTPUT ;
    USE SIGNAL ;
    SHAPE ABUTMENT ;
    PORT
      LAYER metal3 ;
      RECT 0.000 153.265 0.070 153.335 ;
    END
  END rd_out[90]
  PIN rd_out[91]
    DIRECTION OUTPUT ;
    USE SIGNAL ;
    SHAPE ABUTMENT ;
    PORT
      LAYER metal3 ;
      RECT 0.000 153.685 0.070 153.755 ;
    END
  END rd_out[91]
  PIN rd_out[92]
    DIRECTION OUTPUT ;
    USE SIGNAL ;
    SHAPE ABUTMENT ;
    PORT
      LAYER metal3 ;
      RECT 0.000 154.105 0.070 154.175 ;
    END
  END rd_out[92]
  PIN rd_out[93]
    DIRECTION OUTPUT ;
    USE SIGNAL ;
    SHAPE ABUTMENT ;
    PORT
      LAYER metal3 ;
      RECT 0.000 154.525 0.070 154.595 ;
    END
  END rd_out[93]
  PIN rd_out[94]
    DIRECTION OUTPUT ;
    USE SIGNAL ;
    SHAPE ABUTMENT ;
    PORT
      LAYER metal3 ;
      RECT 0.000 154.945 0.070 155.015 ;
    END
  END rd_out[94]
  PIN rd_out[95]
    DIRECTION OUTPUT ;
    USE SIGNAL ;
    SHAPE ABUTMENT ;
    PORT
      LAYER metal3 ;
      RECT 0.000 155.365 0.070 155.435 ;
    END
  END rd_out[95]
  PIN rd_out[96]
    DIRECTION OUTPUT ;
    USE SIGNAL ;
    SHAPE ABUTMENT ;
    PORT
      LAYER metal3 ;
      RECT 0.000 155.785 0.070 155.855 ;
    END
  END rd_out[96]
  PIN rd_out[97]
    DIRECTION OUTPUT ;
    USE SIGNAL ;
    SHAPE ABUTMENT ;
    PORT
      LAYER metal3 ;
      RECT 0.000 156.205 0.070 156.275 ;
    END
  END rd_out[97]
  PIN rd_out[98]
    DIRECTION OUTPUT ;
    USE SIGNAL ;
    SHAPE ABUTMENT ;
    PORT
      LAYER metal3 ;
      RECT 0.000 156.625 0.070 156.695 ;
    END
  END rd_out[98]
  PIN rd_out[99]
    DIRECTION OUTPUT ;
    USE SIGNAL ;
    SHAPE ABUTMENT ;
    PORT
      LAYER metal3 ;
      RECT 0.000 157.045 0.070 157.115 ;
    END
  END rd_out[99]
  PIN rd_out[100]
    DIRECTION OUTPUT ;
    USE SIGNAL ;
    SHAPE ABUTMENT ;
    PORT
      LAYER metal3 ;
      RECT 0.000 157.465 0.070 157.535 ;
    END
  END rd_out[100]
  PIN rd_out[101]
    DIRECTION OUTPUT ;
    USE SIGNAL ;
    SHAPE ABUTMENT ;
    PORT
      LAYER metal3 ;
      RECT 0.000 157.885 0.070 157.955 ;
    END
  END rd_out[101]
  PIN rd_out[102]
    DIRECTION OUTPUT ;
    USE SIGNAL ;
    SHAPE ABUTMENT ;
    PORT
      LAYER metal3 ;
      RECT 0.000 158.305 0.070 158.375 ;
    END
  END rd_out[102]
  PIN rd_out[103]
    DIRECTION OUTPUT ;
    USE SIGNAL ;
    SHAPE ABUTMENT ;
    PORT
      LAYER metal3 ;
      RECT 0.000 158.725 0.070 158.795 ;
    END
  END rd_out[103]
  PIN rd_out[104]
    DIRECTION OUTPUT ;
    USE SIGNAL ;
    SHAPE ABUTMENT ;
    PORT
      LAYER metal3 ;
      RECT 0.000 159.145 0.070 159.215 ;
    END
  END rd_out[104]
  PIN rd_out[105]
    DIRECTION OUTPUT ;
    USE SIGNAL ;
    SHAPE ABUTMENT ;
    PORT
      LAYER metal3 ;
      RECT 0.000 159.565 0.070 159.635 ;
    END
  END rd_out[105]
  PIN rd_out[106]
    DIRECTION OUTPUT ;
    USE SIGNAL ;
    SHAPE ABUTMENT ;
    PORT
      LAYER metal3 ;
      RECT 0.000 159.985 0.070 160.055 ;
    END
  END rd_out[106]
  PIN rd_out[107]
    DIRECTION OUTPUT ;
    USE SIGNAL ;
    SHAPE ABUTMENT ;
    PORT
      LAYER metal3 ;
      RECT 0.000 160.405 0.070 160.475 ;
    END
  END rd_out[107]
  PIN rd_out[108]
    DIRECTION OUTPUT ;
    USE SIGNAL ;
    SHAPE ABUTMENT ;
    PORT
      LAYER metal3 ;
      RECT 0.000 160.825 0.070 160.895 ;
    END
  END rd_out[108]
  PIN rd_out[109]
    DIRECTION OUTPUT ;
    USE SIGNAL ;
    SHAPE ABUTMENT ;
    PORT
      LAYER metal3 ;
      RECT 0.000 161.245 0.070 161.315 ;
    END
  END rd_out[109]
  PIN rd_out[110]
    DIRECTION OUTPUT ;
    USE SIGNAL ;
    SHAPE ABUTMENT ;
    PORT
      LAYER metal3 ;
      RECT 0.000 161.665 0.070 161.735 ;
    END
  END rd_out[110]
  PIN rd_out[111]
    DIRECTION OUTPUT ;
    USE SIGNAL ;
    SHAPE ABUTMENT ;
    PORT
      LAYER metal3 ;
      RECT 0.000 162.085 0.070 162.155 ;
    END
  END rd_out[111]
  PIN rd_out[112]
    DIRECTION OUTPUT ;
    USE SIGNAL ;
    SHAPE ABUTMENT ;
    PORT
      LAYER metal3 ;
      RECT 0.000 162.505 0.070 162.575 ;
    END
  END rd_out[112]
  PIN rd_out[113]
    DIRECTION OUTPUT ;
    USE SIGNAL ;
    SHAPE ABUTMENT ;
    PORT
      LAYER metal3 ;
      RECT 0.000 162.925 0.070 162.995 ;
    END
  END rd_out[113]
  PIN rd_out[114]
    DIRECTION OUTPUT ;
    USE SIGNAL ;
    SHAPE ABUTMENT ;
    PORT
      LAYER metal3 ;
      RECT 0.000 163.345 0.070 163.415 ;
    END
  END rd_out[114]
  PIN rd_out[115]
    DIRECTION OUTPUT ;
    USE SIGNAL ;
    SHAPE ABUTMENT ;
    PORT
      LAYER metal3 ;
      RECT 0.000 163.765 0.070 163.835 ;
    END
  END rd_out[115]
  PIN rd_out[116]
    DIRECTION OUTPUT ;
    USE SIGNAL ;
    SHAPE ABUTMENT ;
    PORT
      LAYER metal3 ;
      RECT 0.000 164.185 0.070 164.255 ;
    END
  END rd_out[116]
  PIN rd_out[117]
    DIRECTION OUTPUT ;
    USE SIGNAL ;
    SHAPE ABUTMENT ;
    PORT
      LAYER metal3 ;
      RECT 0.000 164.605 0.070 164.675 ;
    END
  END rd_out[117]
  PIN rd_out[118]
    DIRECTION OUTPUT ;
    USE SIGNAL ;
    SHAPE ABUTMENT ;
    PORT
      LAYER metal3 ;
      RECT 0.000 165.025 0.070 165.095 ;
    END
  END rd_out[118]
  PIN rd_out[119]
    DIRECTION OUTPUT ;
    USE SIGNAL ;
    SHAPE ABUTMENT ;
    PORT
      LAYER metal3 ;
      RECT 0.000 165.445 0.070 165.515 ;
    END
  END rd_out[119]
  PIN rd_out[120]
    DIRECTION OUTPUT ;
    USE SIGNAL ;
    SHAPE ABUTMENT ;
    PORT
      LAYER metal3 ;
      RECT 0.000 165.865 0.070 165.935 ;
    END
  END rd_out[120]
  PIN rd_out[121]
    DIRECTION OUTPUT ;
    USE SIGNAL ;
    SHAPE ABUTMENT ;
    PORT
      LAYER metal3 ;
      RECT 0.000 166.285 0.070 166.355 ;
    END
  END rd_out[121]
  PIN rd_out[122]
    DIRECTION OUTPUT ;
    USE SIGNAL ;
    SHAPE ABUTMENT ;
    PORT
      LAYER metal3 ;
      RECT 0.000 166.705 0.070 166.775 ;
    END
  END rd_out[122]
  PIN rd_out[123]
    DIRECTION OUTPUT ;
    USE SIGNAL ;
    SHAPE ABUTMENT ;
    PORT
      LAYER metal3 ;
      RECT 0.000 167.125 0.070 167.195 ;
    END
  END rd_out[123]
  PIN rd_out[124]
    DIRECTION OUTPUT ;
    USE SIGNAL ;
    SHAPE ABUTMENT ;
    PORT
      LAYER metal3 ;
      RECT 0.000 167.545 0.070 167.615 ;
    END
  END rd_out[124]
  PIN rd_out[125]
    DIRECTION OUTPUT ;
    USE SIGNAL ;
    SHAPE ABUTMENT ;
    PORT
      LAYER metal3 ;
      RECT 0.000 167.965 0.070 168.035 ;
    END
  END rd_out[125]
  PIN rd_out[126]
    DIRECTION OUTPUT ;
    USE SIGNAL ;
    SHAPE ABUTMENT ;
    PORT
      LAYER metal3 ;
      RECT 0.000 168.385 0.070 168.455 ;
    END
  END rd_out[126]
  PIN rd_out[127]
    DIRECTION OUTPUT ;
    USE SIGNAL ;
    SHAPE ABUTMENT ;
    PORT
      LAYER metal3 ;
      RECT 0.000 168.805 0.070 168.875 ;
    END
  END rd_out[127]
  PIN r_addr_in[0]
    DIRECTION INPUT ;
    USE SIGNAL ;
    SHAPE ABUTMENT ;
    PORT
      LAYER metal3 ;
      RECT 0.000 169.225 0.070 169.295 ;
    END
  END r_addr_in[0]
  PIN r_addr_in[1]
    DIRECTION INPUT ;
    USE SIGNAL ;
    SHAPE ABUTMENT ;
    PORT
      LAYER metal3 ;
      RECT 0.000 169.645 0.070 169.715 ;
    END
  END r_addr_in[1]
  PIN r_addr_in[2]
    DIRECTION INPUT ;
    USE SIGNAL ;
    SHAPE ABUTMENT ;
    PORT
      LAYER metal3 ;
      RECT 0.000 170.065 0.070 170.135 ;
    END
  END r_addr_in[2]
  PIN r_addr_in[3]
    DIRECTION INPUT ;
    USE SIGNAL ;
    SHAPE ABUTMENT ;
    PORT
      LAYER metal3 ;
      RECT 0.000 170.485 0.070 170.555 ;
    END
  END r_addr_in[3]
  PIN r_addr_in[4]
    DIRECTION INPUT ;
    USE SIGNAL ;
    SHAPE ABUTMENT ;
    PORT
      LAYER metal3 ;
      RECT 0.000 170.905 0.070 170.975 ;
    END
  END r_addr_in[4]
  PIN r_addr_in[5]
    DIRECTION INPUT ;
    USE SIGNAL ;
    SHAPE ABUTMENT ;
    PORT
      LAYER metal3 ;
      RECT 0.000 171.325 0.070 171.395 ;
    END
  END r_addr_in[5]
  PIN r_ce_in
    DIRECTION INPUT ;
    USE SIGNAL ;
    SHAPE ABUTMENT ;
    PORT
      LAYER metal3 ;
      RECT 0.000 171.745 0.070 171.815 ;
    END
  END r_ce_in
  PIN clk
    DIRECTION INPUT ;
    USE SIGNAL ;
    SHAPE ABUTMENT ;
    PORT
      LAYER metal3 ;
      RECT 0.000 175.805 0.070 175.875 ;
    END
  END clk
  PIN VSS
    DIRECTION INOUT ;
    USE GROUND ;
    PORT
      LAYER metal4 ;
      RECT 1.260 1.400 1.540 182.000 ;
      RECT 3.500 1.400 3.780 182.000 ;
      RECT 5.740 1.400 6.020 182.000 ;
      RECT 7.980 1.400 8.260 182.000 ;
      RECT 10.220 1.400 10.500 182.000 ;
      RECT 12.460 1.400 12.740 182.000 ;
      RECT 14.700 1.400 14.980 182.000 ;
      RECT 16.940 1.400 17.220 182.000 ;
      RECT 19.180 1.400 19.460 182.000 ;
      RECT 21.420 1.400 21.700 182.000 ;
      RECT 23.660 1.400 23.940 182.000 ;
      RECT 25.900 1.400 26.180 182.000 ;
      RECT 28.140 1.400 28.420 182.000 ;
      RECT 30.380 1.400 30.660 182.000 ;
      RECT 32.620 1.400 32.900 182.000 ;
      RECT 34.860 1.400 35.140 182.000 ;
      RECT 37.100 1.400 37.380 182.000 ;
      RECT 39.340 1.400 39.620 182.000 ;
      RECT 41.580 1.400 41.860 182.000 ;
      RECT 43.820 1.400 44.100 182.000 ;
      RECT 46.060 1.400 46.340 182.000 ;
      RECT 48.300 1.400 48.580 182.000 ;
      RECT 50.540 1.400 50.820 182.000 ;
      RECT 52.780 1.400 53.060 182.000 ;
      RECT 55.020 1.400 55.300 182.000 ;
      RECT 57.260 1.400 57.540 182.000 ;
      RECT 59.500 1.400 59.780 182.000 ;
      RECT 61.740 1.400 62.020 182.000 ;
      RECT 63.980 1.400 64.260 182.000 ;
      RECT 66.220 1.400 66.500 182.000 ;
      RECT 68.460 1.400 68.740 182.000 ;
      RECT 70.700 1.400 70.980 182.000 ;
      RECT 72.940 1.400 73.220 182.000 ;
      RECT 75.180 1.400 75.460 182.000 ;
      RECT 77.420 1.400 77.700 182.000 ;
      RECT 79.660 1.400 79.940 182.000 ;
      RECT 81.900 1.400 82.180 182.000 ;
      RECT 84.140 1.400 84.420 182.000 ;
      RECT 86.380 1.400 86.660 182.000 ;
      RECT 88.620 1.400 88.900 182.000 ;
      RECT 90.860 1.400 91.140 182.000 ;
      RECT 93.100 1.400 93.380 182.000 ;
      RECT 95.340 1.400 95.620 182.000 ;
      RECT 97.580 1.400 97.860 182.000 ;
      RECT 99.820 1.400 100.100 182.000 ;
      RECT 102.060 1.400 102.340 182.000 ;
      RECT 104.300 1.400 104.580 182.000 ;
      RECT 106.540 1.400 106.820 182.000 ;
      RECT 108.780 1.400 109.060 182.000 ;
      RECT 111.020 1.400 111.300 182.000 ;
      RECT 113.260 1.400 113.540 182.000 ;
      RECT 115.500 1.400 115.780 182.000 ;
      RECT 117.740 1.400 118.020 182.000 ;
    END
  END VSS
  PIN VDD
    DIRECTION INOUT ;
    USE POWER ;
    PORT
      LAYER metal4 ;
      RECT 2.380 1.400 2.660 182.000 ;
      RECT 4.620 1.400 4.900 182.000 ;
      RECT 6.860 1.400 7.140 182.000 ;
      RECT 9.100 1.400 9.380 182.000 ;
      RECT 11.340 1.400 11.620 182.000 ;
      RECT 13.580 1.400 13.860 182.000 ;
      RECT 15.820 1.400 16.100 182.000 ;
      RECT 18.060 1.400 18.340 182.000 ;
      RECT 20.300 1.400 20.580 182.000 ;
      RECT 22.540 1.400 22.820 182.000 ;
      RECT 24.780 1.400 25.060 182.000 ;
      RECT 27.020 1.400 27.300 182.000 ;
      RECT 29.260 1.400 29.540 182.000 ;
      RECT 31.500 1.400 31.780 182.000 ;
      RECT 33.740 1.400 34.020 182.000 ;
      RECT 35.980 1.400 36.260 182.000 ;
      RECT 38.220 1.400 38.500 182.000 ;
      RECT 40.460 1.400 40.740 182.000 ;
      RECT 42.700 1.400 42.980 182.000 ;
      RECT 44.940 1.400 45.220 182.000 ;
      RECT 47.180 1.400 47.460 182.000 ;
      RECT 49.420 1.400 49.700 182.000 ;
      RECT 51.660 1.400 51.940 182.000 ;
      RECT 53.900 1.400 54.180 182.000 ;
      RECT 56.140 1.400 56.420 182.000 ;
      RECT 58.380 1.400 58.660 182.000 ;
      RECT 60.620 1.400 60.900 182.000 ;
      RECT 62.860 1.400 63.140 182.000 ;
      RECT 65.100 1.400 65.380 182.000 ;
      RECT 67.340 1.400 67.620 182.000 ;
      RECT 69.580 1.400 69.860 182.000 ;
      RECT 71.820 1.400 72.100 182.000 ;
      RECT 74.060 1.400 74.340 182.000 ;
      RECT 76.300 1.400 76.580 182.000 ;
      RECT 78.540 1.400 78.820 182.000 ;
      RECT 80.780 1.400 81.060 182.000 ;
      RECT 83.020 1.400 83.300 182.000 ;
      RECT 85.260 1.400 85.540 182.000 ;
      RECT 87.500 1.400 87.780 182.000 ;
      RECT 89.740 1.400 90.020 182.000 ;
      RECT 91.980 1.400 92.260 182.000 ;
      RECT 94.220 1.400 94.500 182.000 ;
      RECT 96.460 1.400 96.740 182.000 ;
      RECT 98.700 1.400 98.980 182.000 ;
      RECT 100.940 1.400 101.220 182.000 ;
      RECT 103.180 1.400 103.460 182.000 ;
      RECT 105.420 1.400 105.700 182.000 ;
      RECT 107.660 1.400 107.940 182.000 ;
      RECT 109.900 1.400 110.180 182.000 ;
      RECT 112.140 1.400 112.420 182.000 ;
      RECT 114.380 1.400 114.660 182.000 ;
      RECT 116.620 1.400 116.900 182.000 ;
      RECT 118.860 1.400 119.140 182.000 ;
    END
  END VDD
  OBS
    LAYER metal1 ;
    RECT 0 0 121.220 183.400 ;
    LAYER metal2 ;
    RECT 0 0 121.220 183.400 ;
    LAYER metal3 ;
    RECT 0.070 0 121.220 183.400 ;
    RECT 0 0.000 0.070 1.365 ;
    RECT 0 1.435 0.070 1.785 ;
    RECT 0 1.855 0.070 2.205 ;
    RECT 0 2.275 0.070 2.625 ;
    RECT 0 2.695 0.070 3.045 ;
    RECT 0 3.115 0.070 3.465 ;
    RECT 0 3.535 0.070 3.885 ;
    RECT 0 3.955 0.070 4.305 ;
    RECT 0 4.375 0.070 4.725 ;
    RECT 0 4.795 0.070 5.145 ;
    RECT 0 5.215 0.070 5.565 ;
    RECT 0 5.635 0.070 5.985 ;
    RECT 0 6.055 0.070 6.405 ;
    RECT 0 6.475 0.070 6.825 ;
    RECT 0 6.895 0.070 7.245 ;
    RECT 0 7.315 0.070 7.665 ;
    RECT 0 7.735 0.070 8.085 ;
    RECT 0 8.155 0.070 8.505 ;
    RECT 0 8.575 0.070 8.925 ;
    RECT 0 8.995 0.070 9.345 ;
    RECT 0 9.415 0.070 9.765 ;
    RECT 0 9.835 0.070 10.185 ;
    RECT 0 10.255 0.070 10.605 ;
    RECT 0 10.675 0.070 11.025 ;
    RECT 0 11.095 0.070 11.445 ;
    RECT 0 11.515 0.070 11.865 ;
    RECT 0 11.935 0.070 12.285 ;
    RECT 0 12.355 0.070 12.705 ;
    RECT 0 12.775 0.070 13.125 ;
    RECT 0 13.195 0.070 13.545 ;
    RECT 0 13.615 0.070 13.965 ;
    RECT 0 14.035 0.070 14.385 ;
    RECT 0 14.455 0.070 14.805 ;
    RECT 0 14.875 0.070 15.225 ;
    RECT 0 15.295 0.070 15.645 ;
    RECT 0 15.715 0.070 16.065 ;
    RECT 0 16.135 0.070 16.485 ;
    RECT 0 16.555 0.070 16.905 ;
    RECT 0 16.975 0.070 17.325 ;
    RECT 0 17.395 0.070 17.745 ;
    RECT 0 17.815 0.070 18.165 ;
    RECT 0 18.235 0.070 18.585 ;
    RECT 0 18.655 0.070 19.005 ;
    RECT 0 19.075 0.070 19.425 ;
    RECT 0 19.495 0.070 19.845 ;
    RECT 0 19.915 0.070 20.265 ;
    RECT 0 20.335 0.070 20.685 ;
    RECT 0 20.755 0.070 21.105 ;
    RECT 0 21.175 0.070 21.525 ;
    RECT 0 21.595 0.070 21.945 ;
    RECT 0 22.015 0.070 22.365 ;
    RECT 0 22.435 0.070 22.785 ;
    RECT 0 22.855 0.070 23.205 ;
    RECT 0 23.275 0.070 23.625 ;
    RECT 0 23.695 0.070 24.045 ;
    RECT 0 24.115 0.070 24.465 ;
    RECT 0 24.535 0.070 24.885 ;
    RECT 0 24.955 0.070 25.305 ;
    RECT 0 25.375 0.070 25.725 ;
    RECT 0 25.795 0.070 26.145 ;
    RECT 0 26.215 0.070 26.565 ;
    RECT 0 26.635 0.070 26.985 ;
    RECT 0 27.055 0.070 27.405 ;
    RECT 0 27.475 0.070 27.825 ;
    RECT 0 27.895 0.070 28.245 ;
    RECT 0 28.315 0.070 28.665 ;
    RECT 0 28.735 0.070 29.085 ;
    RECT 0 29.155 0.070 29.505 ;
    RECT 0 29.575 0.070 29.925 ;
    RECT 0 29.995 0.070 30.345 ;
    RECT 0 30.415 0.070 30.765 ;
    RECT 0 30.835 0.070 31.185 ;
    RECT 0 31.255 0.070 31.605 ;
    RECT 0 31.675 0.070 32.025 ;
    RECT 0 32.095 0.070 32.445 ;
    RECT 0 32.515 0.070 32.865 ;
    RECT 0 32.935 0.070 33.285 ;
    RECT 0 33.355 0.070 33.705 ;
    RECT 0 33.775 0.070 34.125 ;
    RECT 0 34.195 0.070 34.545 ;
    RECT 0 34.615 0.070 34.965 ;
    RECT 0 35.035 0.070 35.385 ;
    RECT 0 35.455 0.070 35.805 ;
    RECT 0 35.875 0.070 36.225 ;
    RECT 0 36.295 0.070 36.645 ;
    RECT 0 36.715 0.070 37.065 ;
    RECT 0 37.135 0.070 37.485 ;
    RECT 0 37.555 0.070 37.905 ;
    RECT 0 37.975 0.070 38.325 ;
    RECT 0 38.395 0.070 38.745 ;
    RECT 0 38.815 0.070 39.165 ;
    RECT 0 39.235 0.070 39.585 ;
    RECT 0 39.655 0.070 40.005 ;
    RECT 0 40.075 0.070 40.425 ;
    RECT 0 40.495 0.070 40.845 ;
    RECT 0 40.915 0.070 41.265 ;
    RECT 0 41.335 0.070 41.685 ;
    RECT 0 41.755 0.070 42.105 ;
    RECT 0 42.175 0.070 42.525 ;
    RECT 0 42.595 0.070 42.945 ;
    RECT 0 43.015 0.070 43.365 ;
    RECT 0 43.435 0.070 43.785 ;
    RECT 0 43.855 0.070 44.205 ;
    RECT 0 44.275 0.070 44.625 ;
    RECT 0 44.695 0.070 45.045 ;
    RECT 0 45.115 0.070 45.465 ;
    RECT 0 45.535 0.070 45.885 ;
    RECT 0 45.955 0.070 46.305 ;
    RECT 0 46.375 0.070 46.725 ;
    RECT 0 46.795 0.070 47.145 ;
    RECT 0 47.215 0.070 47.565 ;
    RECT 0 47.635 0.070 47.985 ;
    RECT 0 48.055 0.070 48.405 ;
    RECT 0 48.475 0.070 48.825 ;
    RECT 0 48.895 0.070 49.245 ;
    RECT 0 49.315 0.070 49.665 ;
    RECT 0 49.735 0.070 50.085 ;
    RECT 0 50.155 0.070 50.505 ;
    RECT 0 50.575 0.070 50.925 ;
    RECT 0 50.995 0.070 51.345 ;
    RECT 0 51.415 0.070 51.765 ;
    RECT 0 51.835 0.070 52.185 ;
    RECT 0 52.255 0.070 52.605 ;
    RECT 0 52.675 0.070 53.025 ;
    RECT 0 53.095 0.070 53.445 ;
    RECT 0 53.515 0.070 53.865 ;
    RECT 0 53.935 0.070 54.285 ;
    RECT 0 54.355 0.070 54.705 ;
    RECT 0 54.775 0.070 55.125 ;
    RECT 0 55.195 0.070 55.545 ;
    RECT 0 55.615 0.070 55.965 ;
    RECT 0 56.035 0.070 56.385 ;
    RECT 0 56.455 0.070 56.805 ;
    RECT 0 56.875 0.070 57.225 ;
    RECT 0 57.295 0.070 57.645 ;
    RECT 0 57.715 0.070 58.065 ;
    RECT 0 58.135 0.070 58.485 ;
    RECT 0 58.555 0.070 58.905 ;
    RECT 0 58.975 0.070 59.325 ;
    RECT 0 59.395 0.070 59.745 ;
    RECT 0 59.815 0.070 60.165 ;
    RECT 0 60.235 0.070 60.585 ;
    RECT 0 60.655 0.070 61.005 ;
    RECT 0 61.075 0.070 61.425 ;
    RECT 0 61.495 0.070 61.845 ;
    RECT 0 61.915 0.070 62.265 ;
    RECT 0 62.335 0.070 62.685 ;
    RECT 0 62.755 0.070 63.105 ;
    RECT 0 63.175 0.070 63.525 ;
    RECT 0 63.595 0.070 63.945 ;
    RECT 0 64.015 0.070 64.365 ;
    RECT 0 64.435 0.070 64.785 ;
    RECT 0 64.855 0.070 65.205 ;
    RECT 0 65.275 0.070 65.625 ;
    RECT 0 65.695 0.070 66.045 ;
    RECT 0 66.115 0.070 66.465 ;
    RECT 0 66.535 0.070 66.885 ;
    RECT 0 66.955 0.070 67.305 ;
    RECT 0 67.375 0.070 67.725 ;
    RECT 0 67.795 0.070 68.145 ;
    RECT 0 68.215 0.070 68.565 ;
    RECT 0 68.635 0.070 68.985 ;
    RECT 0 69.055 0.070 69.405 ;
    RECT 0 69.475 0.070 69.825 ;
    RECT 0 69.895 0.070 70.245 ;
    RECT 0 70.315 0.070 70.665 ;
    RECT 0 70.735 0.070 71.085 ;
    RECT 0 71.155 0.070 71.505 ;
    RECT 0 71.575 0.070 71.925 ;
    RECT 0 71.995 0.070 72.345 ;
    RECT 0 72.415 0.070 72.765 ;
    RECT 0 72.835 0.070 73.185 ;
    RECT 0 73.255 0.070 73.605 ;
    RECT 0 73.675 0.070 74.025 ;
    RECT 0 74.095 0.070 74.445 ;
    RECT 0 74.515 0.070 74.865 ;
    RECT 0 74.935 0.070 75.285 ;
    RECT 0 75.355 0.070 75.705 ;
    RECT 0 75.775 0.070 76.125 ;
    RECT 0 76.195 0.070 76.545 ;
    RECT 0 76.615 0.070 76.965 ;
    RECT 0 77.035 0.070 77.385 ;
    RECT 0 77.455 0.070 77.805 ;
    RECT 0 77.875 0.070 78.225 ;
    RECT 0 78.295 0.070 78.645 ;
    RECT 0 78.715 0.070 79.065 ;
    RECT 0 79.135 0.070 79.485 ;
    RECT 0 79.555 0.070 79.905 ;
    RECT 0 79.975 0.070 80.325 ;
    RECT 0 80.395 0.070 80.745 ;
    RECT 0 80.815 0.070 81.165 ;
    RECT 0 81.235 0.070 81.585 ;
    RECT 0 81.655 0.070 82.005 ;
    RECT 0 82.075 0.070 82.425 ;
    RECT 0 82.495 0.070 82.845 ;
    RECT 0 82.915 0.070 83.265 ;
    RECT 0 83.335 0.070 83.685 ;
    RECT 0 83.755 0.070 84.105 ;
    RECT 0 84.175 0.070 84.525 ;
    RECT 0 84.595 0.070 84.945 ;
    RECT 0 85.015 0.070 85.365 ;
    RECT 0 85.435 0.070 85.785 ;
    RECT 0 85.855 0.070 86.205 ;
    RECT 0 86.275 0.070 86.625 ;
    RECT 0 86.695 0.070 87.045 ;
    RECT 0 87.115 0.070 87.465 ;
    RECT 0 87.535 0.070 87.885 ;
    RECT 0 87.955 0.070 88.305 ;
    RECT 0 88.375 0.070 88.725 ;
    RECT 0 88.795 0.070 89.145 ;
    RECT 0 89.215 0.070 89.565 ;
    RECT 0 89.635 0.070 89.985 ;
    RECT 0 90.055 0.070 90.405 ;
    RECT 0 90.475 0.070 90.825 ;
    RECT 0 90.895 0.070 91.245 ;
    RECT 0 91.315 0.070 91.665 ;
    RECT 0 91.735 0.070 92.085 ;
    RECT 0 92.155 0.070 92.505 ;
    RECT 0 92.575 0.070 92.925 ;
    RECT 0 92.995 0.070 93.345 ;
    RECT 0 93.415 0.070 93.765 ;
    RECT 0 93.835 0.070 94.185 ;
    RECT 0 94.255 0.070 94.605 ;
    RECT 0 94.675 0.070 95.025 ;
    RECT 0 95.095 0.070 95.445 ;
    RECT 0 95.515 0.070 95.865 ;
    RECT 0 95.935 0.070 96.285 ;
    RECT 0 96.355 0.070 96.705 ;
    RECT 0 96.775 0.070 97.125 ;
    RECT 0 97.195 0.070 97.545 ;
    RECT 0 97.615 0.070 97.965 ;
    RECT 0 98.035 0.070 98.385 ;
    RECT 0 98.455 0.070 98.805 ;
    RECT 0 98.875 0.070 99.225 ;
    RECT 0 99.295 0.070 99.645 ;
    RECT 0 99.715 0.070 100.065 ;
    RECT 0 100.135 0.070 100.485 ;
    RECT 0 100.555 0.070 100.905 ;
    RECT 0 100.975 0.070 101.325 ;
    RECT 0 101.395 0.070 101.745 ;
    RECT 0 101.815 0.070 102.165 ;
    RECT 0 102.235 0.070 102.585 ;
    RECT 0 102.655 0.070 103.005 ;
    RECT 0 103.075 0.070 103.425 ;
    RECT 0 103.495 0.070 103.845 ;
    RECT 0 103.915 0.070 104.265 ;
    RECT 0 104.335 0.070 104.685 ;
    RECT 0 104.755 0.070 105.105 ;
    RECT 0 105.175 0.070 105.525 ;
    RECT 0 105.595 0.070 105.945 ;
    RECT 0 106.015 0.070 106.365 ;
    RECT 0 106.435 0.070 106.785 ;
    RECT 0 106.855 0.070 107.205 ;
    RECT 0 107.275 0.070 107.625 ;
    RECT 0 107.695 0.070 108.045 ;
    RECT 0 108.115 0.070 108.465 ;
    RECT 0 108.535 0.070 108.885 ;
    RECT 0 108.955 0.070 109.305 ;
    RECT 0 109.375 0.070 109.725 ;
    RECT 0 109.795 0.070 110.145 ;
    RECT 0 110.215 0.070 110.565 ;
    RECT 0 110.635 0.070 110.985 ;
    RECT 0 111.055 0.070 111.405 ;
    RECT 0 111.475 0.070 115.465 ;
    RECT 0 115.535 0.070 115.885 ;
    RECT 0 115.955 0.070 116.305 ;
    RECT 0 116.375 0.070 116.725 ;
    RECT 0 116.795 0.070 117.145 ;
    RECT 0 117.215 0.070 117.565 ;
    RECT 0 117.635 0.070 117.985 ;
    RECT 0 118.055 0.070 118.405 ;
    RECT 0 118.475 0.070 118.825 ;
    RECT 0 118.895 0.070 119.245 ;
    RECT 0 119.315 0.070 119.665 ;
    RECT 0 119.735 0.070 120.085 ;
    RECT 0 120.155 0.070 120.505 ;
    RECT 0 120.575 0.070 120.925 ;
    RECT 0 120.995 0.070 121.345 ;
    RECT 0 121.415 0.070 121.765 ;
    RECT 0 121.835 0.070 122.185 ;
    RECT 0 122.255 0.070 122.605 ;
    RECT 0 122.675 0.070 123.025 ;
    RECT 0 123.095 0.070 123.445 ;
    RECT 0 123.515 0.070 123.865 ;
    RECT 0 123.935 0.070 124.285 ;
    RECT 0 124.355 0.070 124.705 ;
    RECT 0 124.775 0.070 125.125 ;
    RECT 0 125.195 0.070 125.545 ;
    RECT 0 125.615 0.070 125.965 ;
    RECT 0 126.035 0.070 126.385 ;
    RECT 0 126.455 0.070 126.805 ;
    RECT 0 126.875 0.070 127.225 ;
    RECT 0 127.295 0.070 127.645 ;
    RECT 0 127.715 0.070 128.065 ;
    RECT 0 128.135 0.070 128.485 ;
    RECT 0 128.555 0.070 128.905 ;
    RECT 0 128.975 0.070 129.325 ;
    RECT 0 129.395 0.070 129.745 ;
    RECT 0 129.815 0.070 130.165 ;
    RECT 0 130.235 0.070 130.585 ;
    RECT 0 130.655 0.070 131.005 ;
    RECT 0 131.075 0.070 131.425 ;
    RECT 0 131.495 0.070 131.845 ;
    RECT 0 131.915 0.070 132.265 ;
    RECT 0 132.335 0.070 132.685 ;
    RECT 0 132.755 0.070 133.105 ;
    RECT 0 133.175 0.070 133.525 ;
    RECT 0 133.595 0.070 133.945 ;
    RECT 0 134.015 0.070 134.365 ;
    RECT 0 134.435 0.070 134.785 ;
    RECT 0 134.855 0.070 135.205 ;
    RECT 0 135.275 0.070 135.625 ;
    RECT 0 135.695 0.070 136.045 ;
    RECT 0 136.115 0.070 136.465 ;
    RECT 0 136.535 0.070 136.885 ;
    RECT 0 136.955 0.070 137.305 ;
    RECT 0 137.375 0.070 137.725 ;
    RECT 0 137.795 0.070 138.145 ;
    RECT 0 138.215 0.070 138.565 ;
    RECT 0 138.635 0.070 138.985 ;
    RECT 0 139.055 0.070 139.405 ;
    RECT 0 139.475 0.070 139.825 ;
    RECT 0 139.895 0.070 140.245 ;
    RECT 0 140.315 0.070 140.665 ;
    RECT 0 140.735 0.070 141.085 ;
    RECT 0 141.155 0.070 141.505 ;
    RECT 0 141.575 0.070 141.925 ;
    RECT 0 141.995 0.070 142.345 ;
    RECT 0 142.415 0.070 142.765 ;
    RECT 0 142.835 0.070 143.185 ;
    RECT 0 143.255 0.070 143.605 ;
    RECT 0 143.675 0.070 144.025 ;
    RECT 0 144.095 0.070 144.445 ;
    RECT 0 144.515 0.070 144.865 ;
    RECT 0 144.935 0.070 145.285 ;
    RECT 0 145.355 0.070 145.705 ;
    RECT 0 145.775 0.070 146.125 ;
    RECT 0 146.195 0.070 146.545 ;
    RECT 0 146.615 0.070 146.965 ;
    RECT 0 147.035 0.070 147.385 ;
    RECT 0 147.455 0.070 147.805 ;
    RECT 0 147.875 0.070 148.225 ;
    RECT 0 148.295 0.070 148.645 ;
    RECT 0 148.715 0.070 149.065 ;
    RECT 0 149.135 0.070 149.485 ;
    RECT 0 149.555 0.070 149.905 ;
    RECT 0 149.975 0.070 150.325 ;
    RECT 0 150.395 0.070 150.745 ;
    RECT 0 150.815 0.070 151.165 ;
    RECT 0 151.235 0.070 151.585 ;
    RECT 0 151.655 0.070 152.005 ;
    RECT 0 152.075 0.070 152.425 ;
    RECT 0 152.495 0.070 152.845 ;
    RECT 0 152.915 0.070 153.265 ;
    RECT 0 153.335 0.070 153.685 ;
    RECT 0 153.755 0.070 154.105 ;
    RECT 0 154.175 0.070 154.525 ;
    RECT 0 154.595 0.070 154.945 ;
    RECT 0 155.015 0.070 155.365 ;
    RECT 0 155.435 0.070 155.785 ;
    RECT 0 155.855 0.070 156.205 ;
    RECT 0 156.275 0.070 156.625 ;
    RECT 0 156.695 0.070 157.045 ;
    RECT 0 157.115 0.070 157.465 ;
    RECT 0 157.535 0.070 157.885 ;
    RECT 0 157.955 0.070 158.305 ;
    RECT 0 158.375 0.070 158.725 ;
    RECT 0 158.795 0.070 159.145 ;
    RECT 0 159.215 0.070 159.565 ;
    RECT 0 159.635 0.070 159.985 ;
    RECT 0 160.055 0.070 160.405 ;
    RECT 0 160.475 0.070 160.825 ;
    RECT 0 160.895 0.070 161.245 ;
    RECT 0 161.315 0.070 161.665 ;
    RECT 0 161.735 0.070 162.085 ;
    RECT 0 162.155 0.070 162.505 ;
    RECT 0 162.575 0.070 162.925 ;
    RECT 0 162.995 0.070 163.345 ;
    RECT 0 163.415 0.070 163.765 ;
    RECT 0 163.835 0.070 164.185 ;
    RECT 0 164.255 0.070 164.605 ;
    RECT 0 164.675 0.070 165.025 ;
    RECT 0 165.095 0.070 165.445 ;
    RECT 0 165.515 0.070 165.865 ;
    RECT 0 165.935 0.070 166.285 ;
    RECT 0 166.355 0.070 166.705 ;
    RECT 0 166.775 0.070 167.125 ;
    RECT 0 167.195 0.070 167.545 ;
    RECT 0 167.615 0.070 167.965 ;
    RECT 0 168.035 0.070 168.385 ;
    RECT 0 168.455 0.070 168.805 ;
    RECT 0 168.875 0.070 169.225 ;
    RECT 0 169.295 0.070 169.645 ;
    RECT 0 169.715 0.070 170.065 ;
    RECT 0 170.135 0.070 170.485 ;
    RECT 0 170.555 0.070 170.905 ;
    RECT 0 170.975 0.070 171.325 ;
    RECT 0 171.395 0.070 171.745 ;
    RECT 0 171.815 0.070 175.805 ;
    RECT 0 175.875 0.070 183.400 ;
    LAYER metal4 ;
    RECT 0 0 121.220 1.400 ;
    RECT 0 182.000 121.220 183.400 ;
    RECT 0.000 1.400 1.260 182.000 ;
    RECT 1.540 1.400 2.380 182.000 ;
    RECT 2.660 1.400 3.500 182.000 ;
    RECT 3.780 1.400 4.620 182.000 ;
    RECT 4.900 1.400 5.740 182.000 ;
    RECT 6.020 1.400 6.860 182.000 ;
    RECT 7.140 1.400 7.980 182.000 ;
    RECT 8.260 1.400 9.100 182.000 ;
    RECT 9.380 1.400 10.220 182.000 ;
    RECT 10.500 1.400 11.340 182.000 ;
    RECT 11.620 1.400 12.460 182.000 ;
    RECT 12.740 1.400 13.580 182.000 ;
    RECT 13.860 1.400 14.700 182.000 ;
    RECT 14.980 1.400 15.820 182.000 ;
    RECT 16.100 1.400 16.940 182.000 ;
    RECT 17.220 1.400 18.060 182.000 ;
    RECT 18.340 1.400 19.180 182.000 ;
    RECT 19.460 1.400 20.300 182.000 ;
    RECT 20.580 1.400 21.420 182.000 ;
    RECT 21.700 1.400 22.540 182.000 ;
    RECT 22.820 1.400 23.660 182.000 ;
    RECT 23.940 1.400 24.780 182.000 ;
    RECT 25.060 1.400 25.900 182.000 ;
    RECT 26.180 1.400 27.020 182.000 ;
    RECT 27.300 1.400 28.140 182.000 ;
    RECT 28.420 1.400 29.260 182.000 ;
    RECT 29.540 1.400 30.380 182.000 ;
    RECT 30.660 1.400 31.500 182.000 ;
    RECT 31.780 1.400 32.620 182.000 ;
    RECT 32.900 1.400 33.740 182.000 ;
    RECT 34.020 1.400 34.860 182.000 ;
    RECT 35.140 1.400 35.980 182.000 ;
    RECT 36.260 1.400 37.100 182.000 ;
    RECT 37.380 1.400 38.220 182.000 ;
    RECT 38.500 1.400 39.340 182.000 ;
    RECT 39.620 1.400 40.460 182.000 ;
    RECT 40.740 1.400 41.580 182.000 ;
    RECT 41.860 1.400 42.700 182.000 ;
    RECT 42.980 1.400 43.820 182.000 ;
    RECT 44.100 1.400 44.940 182.000 ;
    RECT 45.220 1.400 46.060 182.000 ;
    RECT 46.340 1.400 47.180 182.000 ;
    RECT 47.460 1.400 48.300 182.000 ;
    RECT 48.580 1.400 49.420 182.000 ;
    RECT 49.700 1.400 50.540 182.000 ;
    RECT 50.820 1.400 51.660 182.000 ;
    RECT 51.940 1.400 52.780 182.000 ;
    RECT 53.060 1.400 53.900 182.000 ;
    RECT 54.180 1.400 55.020 182.000 ;
    RECT 55.300 1.400 56.140 182.000 ;
    RECT 56.420 1.400 57.260 182.000 ;
    RECT 57.540 1.400 58.380 182.000 ;
    RECT 58.660 1.400 59.500 182.000 ;
    RECT 59.780 1.400 60.620 182.000 ;
    RECT 60.900 1.400 61.740 182.000 ;
    RECT 62.020 1.400 62.860 182.000 ;
    RECT 63.140 1.400 63.980 182.000 ;
    RECT 64.260 1.400 65.100 182.000 ;
    RECT 65.380 1.400 66.220 182.000 ;
    RECT 66.500 1.400 67.340 182.000 ;
    RECT 67.620 1.400 68.460 182.000 ;
    RECT 68.740 1.400 69.580 182.000 ;
    RECT 69.860 1.400 70.700 182.000 ;
    RECT 70.980 1.400 71.820 182.000 ;
    RECT 72.100 1.400 72.940 182.000 ;
    RECT 73.220 1.400 74.060 182.000 ;
    RECT 74.340 1.400 75.180 182.000 ;
    RECT 75.460 1.400 76.300 182.000 ;
    RECT 76.580 1.400 77.420 182.000 ;
    RECT 77.700 1.400 78.540 182.000 ;
    RECT 78.820 1.400 79.660 182.000 ;
    RECT 79.940 1.400 80.780 182.000 ;
    RECT 81.060 1.400 81.900 182.000 ;
    RECT 82.180 1.400 83.020 182.000 ;
    RECT 83.300 1.400 84.140 182.000 ;
    RECT 84.420 1.400 85.260 182.000 ;
    RECT 85.540 1.400 86.380 182.000 ;
    RECT 86.660 1.400 87.500 182.000 ;
    RECT 87.780 1.400 88.620 182.000 ;
    RECT 88.900 1.400 89.740 182.000 ;
    RECT 90.020 1.400 90.860 182.000 ;
    RECT 91.140 1.400 91.980 182.000 ;
    RECT 92.260 1.400 93.100 182.000 ;
    RECT 93.380 1.400 94.220 182.000 ;
    RECT 94.500 1.400 95.340 182.000 ;
    RECT 95.620 1.400 96.460 182.000 ;
    RECT 96.740 1.400 97.580 182.000 ;
    RECT 97.860 1.400 98.700 182.000 ;
    RECT 98.980 1.400 99.820 182.000 ;
    RECT 100.100 1.400 100.940 182.000 ;
    RECT 101.220 1.400 102.060 182.000 ;
    RECT 102.340 1.400 103.180 182.000 ;
    RECT 103.460 1.400 104.300 182.000 ;
    RECT 104.580 1.400 105.420 182.000 ;
    RECT 105.700 1.400 106.540 182.000 ;
    RECT 106.820 1.400 107.660 182.000 ;
    RECT 107.940 1.400 108.780 182.000 ;
    RECT 109.060 1.400 109.900 182.000 ;
    RECT 110.180 1.400 111.020 182.000 ;
    RECT 111.300 1.400 112.140 182.000 ;
    RECT 112.420 1.400 113.260 182.000 ;
    RECT 113.540 1.400 114.380 182.000 ;
    RECT 114.660 1.400 115.500 182.000 ;
    RECT 115.780 1.400 116.620 182.000 ;
    RECT 116.900 1.400 117.740 182.000 ;
    RECT 118.020 1.400 118.860 182.000 ;
    RECT 119.140 1.400 121.220 182.000 ;
    LAYER OVERLAP ;
    RECT 0 0 121.220 183.400 ;
  END
END sram_64x128_1r1w

END LIBRARY
